UNITS
  DATABASE MICRONS 1000 ;
END UNITS


VERSION 5.7 ;
NAMESCASESENSITIVE ON ;
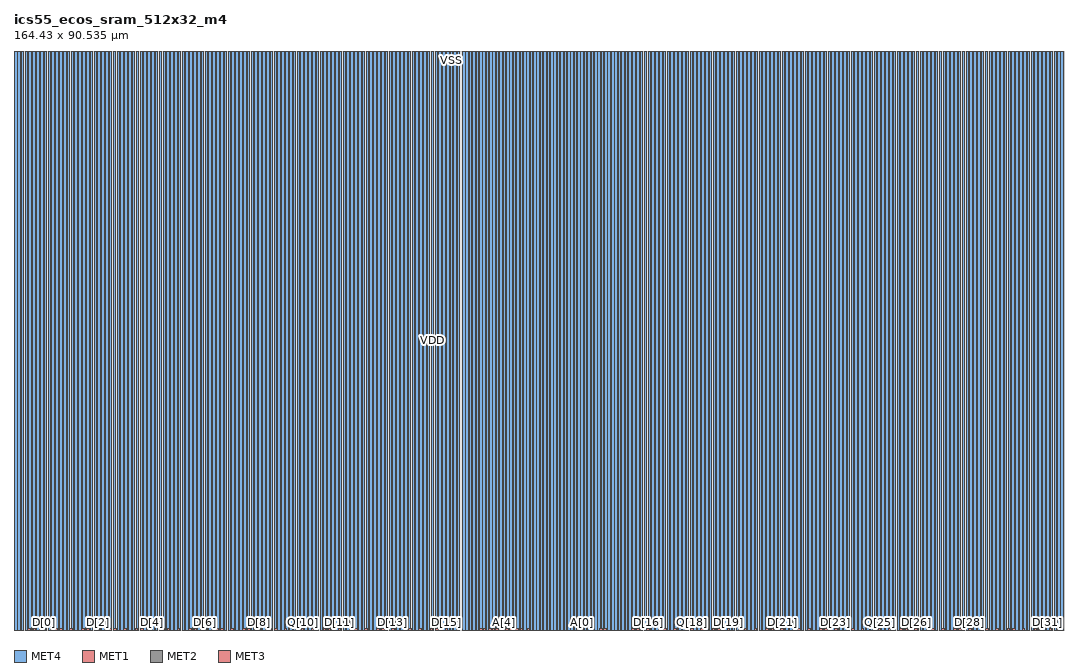
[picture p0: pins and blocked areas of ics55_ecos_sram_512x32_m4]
MACRO ics55_ecos_sram_512x32_m4
CLASS BLOCK ;
FOREIGN ics55_ecos_sram_512x32_m4 0.000 0.000 ;
ORIGIN 0.000 0.000 ;
SIZE 164.430 BY 90.535 ;
SYMMETRY X Y R90 ;

PIN VDD
  DIRECTION INOUT ;
  USE POWER ;
  PORT
    LAYER MET4 ;
    RECT 0.605 0.000 1.015 90.535 ;
    RECT 1.735 0.000 2.145 90.535 ;
    RECT 2.335 0.000 2.745 90.535 ;
    RECT 3.535 0.000 3.945 90.535 ;
    RECT 4.135 0.000 4.545 90.535 ;
    RECT 4.735 0.000 5.145 90.535 ;
    RECT 5.935 0.000 6.345 90.535 ;
    RECT 6.535 0.000 6.945 90.535 ;
    RECT 7.735 0.000 8.145 90.535 ;
    RECT 8.335 0.000 8.745 90.535 ;
    RECT 8.935 0.000 9.345 90.535 ;
    RECT 10.135 0.000 10.545 90.535 ;
    RECT 10.735 0.000 11.145 90.535 ;
    RECT 11.935 0.000 12.345 90.535 ;
    RECT 12.535 0.000 12.945 90.535 ;
    RECT 13.135 0.000 13.545 90.535 ;
    RECT 14.335 0.000 14.745 90.535 ;
    RECT 14.935 0.000 15.345 90.535 ;
    RECT 16.135 0.000 16.545 90.535 ;
    RECT 16.735 0.000 17.145 90.535 ;
    RECT 17.335 0.000 17.745 90.535 ;
    RECT 18.535 0.000 18.945 90.535 ;
    RECT 19.135 0.000 19.545 90.535 ;
    RECT 20.335 0.000 20.745 90.535 ;
    RECT 20.935 0.000 21.345 90.535 ;
    RECT 21.535 0.000 21.945 90.535 ;
    RECT 22.735 0.000 23.145 90.535 ;
    RECT 23.335 0.000 23.745 90.535 ;
    RECT 24.535 0.000 24.945 90.535 ;
    RECT 25.135 0.000 25.545 90.535 ;
    RECT 25.735 0.000 26.145 90.535 ;
    RECT 26.935 0.000 27.345 90.535 ;
    RECT 27.535 0.000 27.945 90.535 ;
    RECT 28.735 0.000 29.145 90.535 ;
    RECT 29.335 0.000 29.745 90.535 ;
    RECT 29.935 0.000 30.345 90.535 ;
    RECT 31.135 0.000 31.545 90.535 ;
    RECT 31.735 0.000 32.145 90.535 ;
    RECT 32.935 0.000 33.345 90.535 ;
    RECT 33.535 0.000 33.945 90.535 ;
    RECT 34.135 0.000 34.545 90.535 ;
    RECT 35.335 0.000 35.745 90.535 ;
    RECT 35.935 0.000 36.345 90.535 ;
    RECT 37.135 0.000 37.545 90.535 ;
    RECT 37.735 0.000 38.145 90.535 ;
    RECT 38.335 0.000 38.745 90.535 ;
    RECT 39.535 0.000 39.945 90.535 ;
    RECT 40.135 0.000 40.545 90.535 ;
    RECT 41.335 0.000 41.745 90.535 ;
    RECT 41.935 0.000 42.345 90.535 ;
    RECT 42.535 0.000 42.945 90.535 ;
    RECT 43.735 0.000 44.145 90.535 ;
    RECT 44.335 0.000 44.745 90.535 ;
    RECT 45.535 0.000 45.945 90.535 ;
    RECT 46.135 0.000 46.545 90.535 ;
    RECT 46.735 0.000 47.145 90.535 ;
    RECT 47.935 0.000 48.345 90.535 ;
    RECT 48.535 0.000 48.945 90.535 ;
    RECT 49.735 0.000 50.145 90.535 ;
    RECT 50.335 0.000 50.745 90.535 ;
    RECT 50.935 0.000 51.345 90.535 ;
    RECT 52.135 0.000 52.545 90.535 ;
    RECT 52.735 0.000 53.145 90.535 ;
    RECT 53.935 0.000 54.345 90.535 ;
    RECT 54.535 0.000 54.945 90.535 ;
    RECT 55.135 0.000 55.545 90.535 ;
    RECT 56.335 0.000 56.745 90.535 ;
    RECT 56.935 0.000 57.345 90.535 ;
    RECT 58.135 0.000 58.545 90.535 ;
    RECT 58.735 0.000 59.145 90.535 ;
    RECT 59.335 0.000 59.745 90.535 ;
    RECT 60.535 0.000 60.945 90.535 ;
    RECT 61.135 0.000 61.545 90.535 ;
    RECT 62.335 0.000 62.745 90.535 ;
    RECT 62.935 0.000 63.345 90.535 ;
    RECT 63.535 0.000 63.945 90.535 ;
    RECT 64.735 0.000 65.145 90.535 ;
    RECT 65.335 0.000 65.745 90.535 ;
    RECT 66.535 0.000 66.945 90.535 ;
    RECT 67.135 0.000 67.545 90.535 ;
    RECT 67.735 0.000 68.145 90.535 ;
    RECT 68.865 0.000 69.275 90.535 ;
    RECT 70.760 0.000 71.170 90.535 ;
    RECT 71.290 0.000 71.700 90.535 ;
    RECT 72.350 0.000 72.760 90.535 ;
    RECT 72.880 0.000 73.290 90.535 ;
    RECT 73.940 0.000 74.350 90.535 ;
    RECT 74.470 0.000 74.880 90.535 ;
    RECT 75.530 0.000 75.940 90.535 ;
    RECT 76.060 0.000 76.470 90.535 ;
    RECT 77.120 0.000 77.530 90.535 ;
    RECT 77.650 0.000 78.060 90.535 ;
    RECT 78.710 0.000 79.120 90.535 ;
    RECT 79.240 0.000 79.650 90.535 ;
    RECT 80.300 0.000 80.710 90.535 ;
    RECT 80.830 0.000 81.240 90.535 ;
    RECT 81.890 0.000 82.300 90.535 ;
    RECT 82.420 0.000 82.830 90.535 ;
    RECT 83.480 0.000 83.890 90.535 ;
    RECT 84.010 0.000 84.420 90.535 ;
    RECT 85.070 0.000 85.480 90.535 ;
    RECT 85.600 0.000 86.010 90.535 ;
    RECT 86.660 0.000 87.070 90.535 ;
    RECT 87.190 0.000 87.600 90.535 ;
    RECT 88.250 0.000 88.660 90.535 ;
    RECT 88.780 0.000 89.190 90.535 ;
    RECT 89.840 0.000 90.250 90.535 ;
    RECT 90.370 0.000 90.780 90.535 ;
    RECT 91.430 0.000 91.840 90.535 ;
    RECT 91.960 0.000 92.370 90.535 ;
    RECT 93.020 0.000 93.430 90.535 ;
    RECT 93.550 0.000 93.960 90.535 ;
    RECT 95.155 0.000 95.565 90.535 ;
    RECT 96.285 0.000 96.695 90.535 ;
    RECT 96.885 0.000 97.295 90.535 ;
    RECT 98.085 0.000 98.495 90.535 ;
    RECT 98.685 0.000 99.095 90.535 ;
    RECT 99.285 0.000 99.695 90.535 ;
    RECT 100.485 0.000 100.895 90.535 ;
    RECT 101.085 0.000 101.495 90.535 ;
    RECT 102.285 0.000 102.695 90.535 ;
    RECT 102.885 0.000 103.295 90.535 ;
    RECT 103.485 0.000 103.895 90.535 ;
    RECT 104.685 0.000 105.095 90.535 ;
    RECT 105.285 0.000 105.695 90.535 ;
    RECT 106.485 0.000 106.895 90.535 ;
    RECT 107.085 0.000 107.495 90.535 ;
    RECT 107.685 0.000 108.095 90.535 ;
    RECT 108.885 0.000 109.295 90.535 ;
    RECT 109.485 0.000 109.895 90.535 ;
    RECT 110.685 0.000 111.095 90.535 ;
    RECT 111.285 0.000 111.695 90.535 ;
    RECT 111.885 0.000 112.295 90.535 ;
    RECT 113.085 0.000 113.495 90.535 ;
    RECT 113.685 0.000 114.095 90.535 ;
    RECT 114.885 0.000 115.295 90.535 ;
    RECT 115.485 0.000 115.895 90.535 ;
    RECT 116.085 0.000 116.495 90.535 ;
    RECT 117.285 0.000 117.695 90.535 ;
    RECT 117.885 0.000 118.295 90.535 ;
    RECT 119.085 0.000 119.495 90.535 ;
    RECT 119.685 0.000 120.095 90.535 ;
    RECT 120.285 0.000 120.695 90.535 ;
    RECT 121.485 0.000 121.895 90.535 ;
    RECT 122.085 0.000 122.495 90.535 ;
    RECT 123.285 0.000 123.695 90.535 ;
    RECT 123.885 0.000 124.295 90.535 ;
    RECT 124.485 0.000 124.895 90.535 ;
    RECT 125.685 0.000 126.095 90.535 ;
    RECT 126.285 0.000 126.695 90.535 ;
    RECT 127.485 0.000 127.895 90.535 ;
    RECT 128.085 0.000 128.495 90.535 ;
    RECT 128.685 0.000 129.095 90.535 ;
    RECT 129.885 0.000 130.295 90.535 ;
    RECT 130.485 0.000 130.895 90.535 ;
    RECT 131.685 0.000 132.095 90.535 ;
    RECT 132.285 0.000 132.695 90.535 ;
    RECT 132.885 0.000 133.295 90.535 ;
    RECT 134.085 0.000 134.495 90.535 ;
    RECT 134.685 0.000 135.095 90.535 ;
    RECT 135.885 0.000 136.295 90.535 ;
    RECT 136.485 0.000 136.895 90.535 ;
    RECT 137.085 0.000 137.495 90.535 ;
    RECT 138.285 0.000 138.695 90.535 ;
    RECT 138.885 0.000 139.295 90.535 ;
    RECT 140.085 0.000 140.495 90.535 ;
    RECT 140.685 0.000 141.095 90.535 ;
    RECT 141.285 0.000 141.695 90.535 ;
    RECT 142.485 0.000 142.895 90.535 ;
    RECT 143.085 0.000 143.495 90.535 ;
    RECT 144.285 0.000 144.695 90.535 ;
    RECT 144.885 0.000 145.295 90.535 ;
    RECT 145.485 0.000 145.895 90.535 ;
    RECT 146.685 0.000 147.095 90.535 ;
    RECT 147.285 0.000 147.695 90.535 ;
    RECT 148.485 0.000 148.895 90.535 ;
    RECT 149.085 0.000 149.495 90.535 ;
    RECT 149.685 0.000 150.095 90.535 ;
    RECT 150.885 0.000 151.295 90.535 ;
    RECT 151.485 0.000 151.895 90.535 ;
    RECT 152.685 0.000 153.095 90.535 ;
    RECT 153.285 0.000 153.695 90.535 ;
    RECT 153.885 0.000 154.295 90.535 ;
    RECT 155.085 0.000 155.495 90.535 ;
    RECT 155.685 0.000 156.095 90.535 ;
    RECT 156.885 0.000 157.295 90.535 ;
    RECT 157.485 0.000 157.895 90.535 ;
    RECT 158.085 0.000 158.495 90.535 ;
    RECT 159.285 0.000 159.695 90.535 ;
    RECT 159.885 0.000 160.295 90.535 ;
    RECT 161.085 0.000 161.495 90.535 ;
    RECT 161.685 0.000 162.095 90.535 ;
    RECT 162.285 0.000 162.695 90.535 ;
    RECT 163.415 0.000 163.825 90.535 ;
  END
END VDD

PIN VSS
  DIRECTION INOUT ;
  USE GROUND ;
  PORT
    LAYER MET4 ;
    RECT 0.075 0.000 0.485 90.535 ;
    RECT 1.135 0.000 1.545 90.535 ;
    RECT 2.935 0.000 3.345 90.535 ;
    RECT 5.335 0.000 5.745 90.535 ;
    RECT 7.135 0.000 7.545 90.535 ;
    RECT 9.535 0.000 9.945 90.535 ;
    RECT 11.335 0.000 11.745 90.535 ;
    RECT 13.735 0.000 14.145 90.535 ;
    RECT 15.535 0.000 15.945 90.535 ;
    RECT 17.935 0.000 18.345 90.535 ;
    RECT 19.735 0.000 20.145 90.535 ;
    RECT 22.135 0.000 22.545 90.535 ;
    RECT 23.935 0.000 24.345 90.535 ;
    RECT 26.335 0.000 26.745 90.535 ;
    RECT 28.135 0.000 28.545 90.535 ;
    RECT 30.535 0.000 30.945 90.535 ;
    RECT 32.335 0.000 32.745 90.535 ;
    RECT 34.735 0.000 35.145 90.535 ;
    RECT 36.535 0.000 36.945 90.535 ;
    RECT 38.935 0.000 39.345 90.535 ;
    RECT 40.735 0.000 41.145 90.535 ;
    RECT 43.135 0.000 43.545 90.535 ;
    RECT 44.935 0.000 45.345 90.535 ;
    RECT 47.335 0.000 47.745 90.535 ;
    RECT 49.135 0.000 49.545 90.535 ;
    RECT 51.535 0.000 51.945 90.535 ;
    RECT 53.335 0.000 53.745 90.535 ;
    RECT 55.735 0.000 56.145 90.535 ;
    RECT 57.535 0.000 57.945 90.535 ;
    RECT 59.935 0.000 60.345 90.535 ;
    RECT 61.735 0.000 62.145 90.535 ;
    RECT 64.135 0.000 64.545 90.535 ;
    RECT 65.935 0.000 66.345 90.535 ;
    RECT 68.335 0.000 68.745 90.535 ;
    RECT 69.395 0.000 69.805 90.535 ;
    RECT 70.230 0.000 70.640 90.535 ;
    RECT 71.820 0.000 72.230 90.535 ;
    RECT 73.410 0.000 73.820 90.535 ;
    RECT 75.000 0.000 75.410 90.535 ;
    RECT 76.590 0.000 77.000 90.535 ;
    RECT 78.180 0.000 78.590 90.535 ;
    RECT 79.770 0.000 80.180 90.535 ;
    RECT 81.360 0.000 81.770 90.535 ;
    RECT 82.950 0.000 83.360 90.535 ;
    RECT 84.540 0.000 84.950 90.535 ;
    RECT 86.130 0.000 86.540 90.535 ;
    RECT 87.720 0.000 88.130 90.535 ;
    RECT 89.310 0.000 89.720 90.535 ;
    RECT 90.900 0.000 91.310 90.535 ;
    RECT 92.490 0.000 92.900 90.535 ;
    RECT 94.080 0.000 94.490 90.535 ;
    RECT 94.625 0.000 95.035 90.535 ;
    RECT 95.685 0.000 96.095 90.535 ;
    RECT 97.485 0.000 97.895 90.535 ;
    RECT 99.885 0.000 100.295 90.535 ;
    RECT 101.685 0.000 102.095 90.535 ;
    RECT 104.085 0.000 104.495 90.535 ;
    RECT 105.885 0.000 106.295 90.535 ;
    RECT 108.285 0.000 108.695 90.535 ;
    RECT 110.085 0.000 110.495 90.535 ;
    RECT 112.485 0.000 112.895 90.535 ;
    RECT 114.285 0.000 114.695 90.535 ;
    RECT 116.685 0.000 117.095 90.535 ;
    RECT 118.485 0.000 118.895 90.535 ;
    RECT 120.885 0.000 121.295 90.535 ;
    RECT 122.685 0.000 123.095 90.535 ;
    RECT 125.085 0.000 125.495 90.535 ;
    RECT 126.885 0.000 127.295 90.535 ;
    RECT 129.285 0.000 129.695 90.535 ;
    RECT 131.085 0.000 131.495 90.535 ;
    RECT 133.485 0.000 133.895 90.535 ;
    RECT 135.285 0.000 135.695 90.535 ;
    RECT 137.685 0.000 138.095 90.535 ;
    RECT 139.485 0.000 139.895 90.535 ;
    RECT 141.885 0.000 142.295 90.535 ;
    RECT 143.685 0.000 144.095 90.535 ;
    RECT 146.085 0.000 146.495 90.535 ;
    RECT 147.885 0.000 148.295 90.535 ;
    RECT 150.285 0.000 150.695 90.535 ;
    RECT 152.085 0.000 152.495 90.535 ;
    RECT 154.485 0.000 154.895 90.535 ;
    RECT 156.285 0.000 156.695 90.535 ;
    RECT 158.685 0.000 159.095 90.535 ;
    RECT 160.485 0.000 160.895 90.535 ;
    RECT 162.885 0.000 163.295 90.535 ;
    RECT 163.945 0.000 164.355 90.535 ;
  END
END VSS

PIN D[0]
  DIRECTION INPUT ;
  PORT
    LAYER MET1 ;
    RECT 4.540 0.000 4.950 0.180 ;
    LAYER MET2 ;
    RECT 4.540 0.000 4.950 0.180 ;
    LAYER MET3 ;
    RECT 4.540 0.000 4.950 0.180 ;
  END
  ANTENNADIFFAREA                0.38930         LAYER MET1 ;
  ANTENNADIFFAREA                0.38930         LAYER MET2 ;
  ANTENNADIFFAREA                0.38930         LAYER MET3 ;
  ANTENNAGATEAREA                0.06300         LAYER MET1 ;
  ANTENNAGATEAREA                0.06300         LAYER MET2 ;
  ANTENNAGATEAREA                0.06300         LAYER MET3 ;
  ANTENNAPARTIALMETALAREA        0.09890         LAYER MET1 ;
  ANTENNAPARTIALMETALAREA        0.10380         LAYER MET2 ;
  ANTENNAMAXAREACAR              0.72381         LAYER MET1 ;
  ANTENNAMAXAREACAR              3.54286         LAYER MET2 ;
  ANTENNAMAXAREACAR              4.71429         LAYER MET3 ;
END D[0]
PIN WEB[0]
  DIRECTION INPUT ;
  PORT
    LAYER MET1 ;
    RECT 2.190 0.000 2.600 0.180 ;
    LAYER MET2 ;
    RECT 2.190 0.000 2.600 0.180 ;
    LAYER MET3 ;
    RECT 2.190 0.000 2.600 0.180 ;
  END
  ANTENNADIFFAREA                0.45930         LAYER MET1 ;
  ANTENNADIFFAREA                0.45930         LAYER MET2 ;
  ANTENNADIFFAREA                0.45930         LAYER MET3 ;
  ANTENNAGATEAREA                0.08100         LAYER MET1 ;
  ANTENNAGATEAREA                0.08100         LAYER MET2 ;
  ANTENNAGATEAREA                0.08100         LAYER MET3 ;
  ANTENNAPARTIALMETALAREA        0.14210         LAYER MET1 ;
  ANTENNAPARTIALMETALAREA        0.09360         LAYER MET2 ;
  ANTENNAMAXAREACAR              1.09630         LAYER MET1 ;
  ANTENNAMAXAREACAR              3.16296         LAYER MET2 ;
  ANTENNAMAXAREACAR              4.07407         LAYER MET3 ;
END WEB[0]
PIN Q[0]
  DIRECTION OUTPUT ;
  PORT
    LAYER MET1 ;
    RECT 3.000 0.000 3.410 0.180 ;
    LAYER MET2 ;
    RECT 3.000 0.000 3.410 0.180 ;
    LAYER MET3 ;
    RECT 3.000 0.000 3.410 0.180 ;
  END
  ANTENNADIFFAREA                0.60000         LAYER MET1 ;
  ANTENNADIFFAREA                0.60000         LAYER MET2 ;
  ANTENNADIFFAREA                0.60000         LAYER MET3 ;
  ANTENNAPARTIALMETALAREA        0.94400         LAYER MET1 ;
  ANTENNAPARTIALMETALAREA        1.33320         LAYER MET2 ;
END Q[0]
PIN D[1]
  DIRECTION INPUT ;
  PORT
    LAYER MET1 ;
    RECT 8.740 0.000 9.150 0.180 ;
    LAYER MET2 ;
    RECT 8.740 0.000 9.150 0.180 ;
    LAYER MET3 ;
    RECT 8.740 0.000 9.150 0.180 ;
  END
  ANTENNADIFFAREA                0.38930         LAYER MET1 ;
  ANTENNADIFFAREA                0.38930         LAYER MET2 ;
  ANTENNADIFFAREA                0.38930         LAYER MET3 ;
  ANTENNAGATEAREA                0.06300         LAYER MET1 ;
  ANTENNAGATEAREA                0.06300         LAYER MET2 ;
  ANTENNAGATEAREA                0.06300         LAYER MET3 ;
  ANTENNAPARTIALMETALAREA        0.09890         LAYER MET1 ;
  ANTENNAPARTIALMETALAREA        0.10380         LAYER MET2 ;
  ANTENNAMAXAREACAR              0.72381         LAYER MET1 ;
  ANTENNAMAXAREACAR              3.54286         LAYER MET2 ;
  ANTENNAMAXAREACAR              4.71429         LAYER MET3 ;
END D[1]
PIN Q[1]
  DIRECTION OUTPUT ;
  PORT
    LAYER MET1 ;
    RECT 7.200 0.000 7.610 0.180 ;
    LAYER MET2 ;
    RECT 7.200 0.000 7.610 0.180 ;
    LAYER MET3 ;
    RECT 7.200 0.000 7.610 0.180 ;
  END
  ANTENNADIFFAREA                0.60000         LAYER MET1 ;
  ANTENNADIFFAREA                0.60000         LAYER MET2 ;
  ANTENNADIFFAREA                0.60000         LAYER MET3 ;
  ANTENNAPARTIALMETALAREA        0.94400         LAYER MET1 ;
  ANTENNAPARTIALMETALAREA        1.33320         LAYER MET2 ;
END Q[1]
PIN WEB[1]
  DIRECTION INPUT ;
  PORT
    LAYER MET1 ;
    RECT 6.390 0.000 6.800 0.180 ;
    LAYER MET2 ;
    RECT 6.390 0.000 6.800 0.180 ;
    LAYER MET3 ;
    RECT 6.390 0.000 6.800 0.180 ;
  END
  ANTENNADIFFAREA                0.45930         LAYER MET1 ;
  ANTENNADIFFAREA                0.45930         LAYER MET2 ;
  ANTENNADIFFAREA                0.45930         LAYER MET3 ;
  ANTENNAGATEAREA                0.08100         LAYER MET1 ;
  ANTENNAGATEAREA                0.08100         LAYER MET2 ;
  ANTENNAGATEAREA                0.08100         LAYER MET3 ;
  ANTENNAPARTIALMETALAREA        0.14210         LAYER MET1 ;
  ANTENNAPARTIALMETALAREA        0.09360         LAYER MET2 ;
  ANTENNAMAXAREACAR              1.09630         LAYER MET1 ;
  ANTENNAMAXAREACAR              3.16296         LAYER MET2 ;
  ANTENNAMAXAREACAR              4.07407         LAYER MET3 ;
END WEB[1]
PIN D[2]
  DIRECTION INPUT ;
  PORT
    LAYER MET1 ;
    RECT 12.940 0.000 13.350 0.180 ;
    LAYER MET2 ;
    RECT 12.940 0.000 13.350 0.180 ;
    LAYER MET3 ;
    RECT 12.940 0.000 13.350 0.180 ;
  END
  ANTENNADIFFAREA                0.38930         LAYER MET1 ;
  ANTENNADIFFAREA                0.38930         LAYER MET2 ;
  ANTENNADIFFAREA                0.38930         LAYER MET3 ;
  ANTENNAGATEAREA                0.06300         LAYER MET1 ;
  ANTENNAGATEAREA                0.06300         LAYER MET2 ;
  ANTENNAGATEAREA                0.06300         LAYER MET3 ;
  ANTENNAPARTIALMETALAREA        0.09890         LAYER MET1 ;
  ANTENNAPARTIALMETALAREA        0.10380         LAYER MET2 ;
  ANTENNAMAXAREACAR              0.72381         LAYER MET1 ;
  ANTENNAMAXAREACAR              3.54286         LAYER MET2 ;
  ANTENNAMAXAREACAR              4.71429         LAYER MET3 ;
END D[2]
PIN Q[2]
  DIRECTION OUTPUT ;
  PORT
    LAYER MET1 ;
    RECT 11.400 0.000 11.810 0.180 ;
    LAYER MET2 ;
    RECT 11.400 0.000 11.810 0.180 ;
    LAYER MET3 ;
    RECT 11.400 0.000 11.810 0.180 ;
  END
  ANTENNADIFFAREA                0.60000         LAYER MET1 ;
  ANTENNADIFFAREA                0.60000         LAYER MET2 ;
  ANTENNADIFFAREA                0.60000         LAYER MET3 ;
  ANTENNAPARTIALMETALAREA        0.94400         LAYER MET1 ;
  ANTENNAPARTIALMETALAREA        1.33320         LAYER MET2 ;
END Q[2]
PIN WEB[2]
  DIRECTION INPUT ;
  PORT
    LAYER MET1 ;
    RECT 10.590 0.000 11.000 0.180 ;
    LAYER MET2 ;
    RECT 10.590 0.000 11.000 0.180 ;
    LAYER MET3 ;
    RECT 10.590 0.000 11.000 0.180 ;
  END
  ANTENNADIFFAREA                0.45930         LAYER MET1 ;
  ANTENNADIFFAREA                0.45930         LAYER MET2 ;
  ANTENNADIFFAREA                0.45930         LAYER MET3 ;
  ANTENNAGATEAREA                0.08100         LAYER MET1 ;
  ANTENNAGATEAREA                0.08100         LAYER MET2 ;
  ANTENNAGATEAREA                0.08100         LAYER MET3 ;
  ANTENNAPARTIALMETALAREA        0.14210         LAYER MET1 ;
  ANTENNAPARTIALMETALAREA        0.09360         LAYER MET2 ;
  ANTENNAMAXAREACAR              1.09630         LAYER MET1 ;
  ANTENNAMAXAREACAR              3.16296         LAYER MET2 ;
  ANTENNAMAXAREACAR              4.07407         LAYER MET3 ;
END WEB[2]
PIN WEB[5]
  DIRECTION INPUT ;
  PORT
    LAYER MET1 ;
    RECT 23.190 0.000 23.600 0.180 ;
    LAYER MET2 ;
    RECT 23.190 0.000 23.600 0.180 ;
    LAYER MET3 ;
    RECT 23.190 0.000 23.600 0.180 ;
  END
  ANTENNADIFFAREA                0.45930         LAYER MET1 ;
  ANTENNADIFFAREA                0.45930         LAYER MET2 ;
  ANTENNADIFFAREA                0.45930         LAYER MET3 ;
  ANTENNAGATEAREA                0.08100         LAYER MET1 ;
  ANTENNAGATEAREA                0.08100         LAYER MET2 ;
  ANTENNAGATEAREA                0.08100         LAYER MET3 ;
  ANTENNAPARTIALMETALAREA        0.14210         LAYER MET1 ;
  ANTENNAPARTIALMETALAREA        0.09360         LAYER MET2 ;
  ANTENNAMAXAREACAR              1.09630         LAYER MET1 ;
  ANTENNAMAXAREACAR              3.16296         LAYER MET2 ;
  ANTENNAMAXAREACAR              4.07407         LAYER MET3 ;
END WEB[5]
PIN D[6]
  DIRECTION INPUT ;
  PORT
    LAYER MET1 ;
    RECT 29.740 0.000 30.150 0.180 ;
    LAYER MET2 ;
    RECT 29.740 0.000 30.150 0.180 ;
    LAYER MET3 ;
    RECT 29.740 0.000 30.150 0.180 ;
  END
  ANTENNADIFFAREA                0.38930         LAYER MET1 ;
  ANTENNADIFFAREA                0.38930         LAYER MET2 ;
  ANTENNADIFFAREA                0.38930         LAYER MET3 ;
  ANTENNAGATEAREA                0.06300         LAYER MET1 ;
  ANTENNAGATEAREA                0.06300         LAYER MET2 ;
  ANTENNAGATEAREA                0.06300         LAYER MET3 ;
  ANTENNAPARTIALMETALAREA        0.09890         LAYER MET1 ;
  ANTENNAPARTIALMETALAREA        0.10380         LAYER MET2 ;
  ANTENNAMAXAREACAR              0.72381         LAYER MET1 ;
  ANTENNAMAXAREACAR              3.54286         LAYER MET2 ;
  ANTENNAMAXAREACAR              4.71429         LAYER MET3 ;
END D[6]
PIN D[3]
  DIRECTION INPUT ;
  PORT
    LAYER MET1 ;
    RECT 17.140 0.000 17.550 0.180 ;
    LAYER MET2 ;
    RECT 17.140 0.000 17.550 0.180 ;
    LAYER MET3 ;
    RECT 17.140 0.000 17.550 0.180 ;
  END
  ANTENNADIFFAREA                0.38930         LAYER MET1 ;
  ANTENNADIFFAREA                0.38930         LAYER MET2 ;
  ANTENNADIFFAREA                0.38930         LAYER MET3 ;
  ANTENNAGATEAREA                0.06300         LAYER MET1 ;
  ANTENNAGATEAREA                0.06300         LAYER MET2 ;
  ANTENNAGATEAREA                0.06300         LAYER MET3 ;
  ANTENNAPARTIALMETALAREA        0.09890         LAYER MET1 ;
  ANTENNAPARTIALMETALAREA        0.10380         LAYER MET2 ;
  ANTENNAMAXAREACAR              0.72381         LAYER MET1 ;
  ANTENNAMAXAREACAR              3.54286         LAYER MET2 ;
  ANTENNAMAXAREACAR              4.71429         LAYER MET3 ;
END D[3]
PIN Q[3]
  DIRECTION OUTPUT ;
  PORT
    LAYER MET1 ;
    RECT 15.600 0.000 16.010 0.180 ;
    LAYER MET2 ;
    RECT 15.600 0.000 16.010 0.180 ;
    LAYER MET3 ;
    RECT 15.600 0.000 16.010 0.180 ;
  END
  ANTENNADIFFAREA                0.60000         LAYER MET1 ;
  ANTENNADIFFAREA                0.60000         LAYER MET2 ;
  ANTENNADIFFAREA                0.60000         LAYER MET3 ;
  ANTENNAPARTIALMETALAREA        0.94400         LAYER MET1 ;
  ANTENNAPARTIALMETALAREA        1.33320         LAYER MET2 ;
END Q[3]
PIN WEB[3]
  DIRECTION INPUT ;
  PORT
    LAYER MET1 ;
    RECT 14.790 0.000 15.200 0.180 ;
    LAYER MET2 ;
    RECT 14.790 0.000 15.200 0.180 ;
    LAYER MET3 ;
    RECT 14.790 0.000 15.200 0.180 ;
  END
  ANTENNADIFFAREA                0.45930         LAYER MET1 ;
  ANTENNADIFFAREA                0.45930         LAYER MET2 ;
  ANTENNADIFFAREA                0.45930         LAYER MET3 ;
  ANTENNAGATEAREA                0.08100         LAYER MET1 ;
  ANTENNAGATEAREA                0.08100         LAYER MET2 ;
  ANTENNAGATEAREA                0.08100         LAYER MET3 ;
  ANTENNAPARTIALMETALAREA        0.14210         LAYER MET1 ;
  ANTENNAPARTIALMETALAREA        0.09360         LAYER MET2 ;
  ANTENNAMAXAREACAR              1.09630         LAYER MET1 ;
  ANTENNAMAXAREACAR              3.16296         LAYER MET2 ;
  ANTENNAMAXAREACAR              4.07407         LAYER MET3 ;
END WEB[3]
PIN D[4]
  DIRECTION INPUT ;
  PORT
    LAYER MET1 ;
    RECT 21.340 0.000 21.750 0.180 ;
    LAYER MET2 ;
    RECT 21.340 0.000 21.750 0.180 ;
    LAYER MET3 ;
    RECT 21.340 0.000 21.750 0.180 ;
  END
  ANTENNADIFFAREA                0.38930         LAYER MET1 ;
  ANTENNADIFFAREA                0.38930         LAYER MET2 ;
  ANTENNADIFFAREA                0.38930         LAYER MET3 ;
  ANTENNAGATEAREA                0.06300         LAYER MET1 ;
  ANTENNAGATEAREA                0.06300         LAYER MET2 ;
  ANTENNAGATEAREA                0.06300         LAYER MET3 ;
  ANTENNAPARTIALMETALAREA        0.09890         LAYER MET1 ;
  ANTENNAPARTIALMETALAREA        0.10380         LAYER MET2 ;
  ANTENNAMAXAREACAR              0.72381         LAYER MET1 ;
  ANTENNAMAXAREACAR              3.54286         LAYER MET2 ;
  ANTENNAMAXAREACAR              4.71429         LAYER MET3 ;
END D[4]
PIN Q[4]
  DIRECTION OUTPUT ;
  PORT
    LAYER MET1 ;
    RECT 19.800 0.000 20.210 0.180 ;
    LAYER MET2 ;
    RECT 19.800 0.000 20.210 0.180 ;
    LAYER MET3 ;
    RECT 19.800 0.000 20.210 0.180 ;
  END
  ANTENNADIFFAREA                0.60000         LAYER MET1 ;
  ANTENNADIFFAREA                0.60000         LAYER MET2 ;
  ANTENNADIFFAREA                0.60000         LAYER MET3 ;
  ANTENNAPARTIALMETALAREA        0.94400         LAYER MET1 ;
  ANTENNAPARTIALMETALAREA        1.33320         LAYER MET2 ;
END Q[4]
PIN WEB[4]
  DIRECTION INPUT ;
  PORT
    LAYER MET1 ;
    RECT 18.990 0.000 19.400 0.180 ;
    LAYER MET2 ;
    RECT 18.990 0.000 19.400 0.180 ;
    LAYER MET3 ;
    RECT 18.990 0.000 19.400 0.180 ;
  END
  ANTENNADIFFAREA                0.45930         LAYER MET1 ;
  ANTENNADIFFAREA                0.45930         LAYER MET2 ;
  ANTENNADIFFAREA                0.45930         LAYER MET3 ;
  ANTENNAGATEAREA                0.08100         LAYER MET1 ;
  ANTENNAGATEAREA                0.08100         LAYER MET2 ;
  ANTENNAGATEAREA                0.08100         LAYER MET3 ;
  ANTENNAPARTIALMETALAREA        0.14210         LAYER MET1 ;
  ANTENNAPARTIALMETALAREA        0.09360         LAYER MET2 ;
  ANTENNAMAXAREACAR              1.09630         LAYER MET1 ;
  ANTENNAMAXAREACAR              3.16296         LAYER MET2 ;
  ANTENNAMAXAREACAR              4.07407         LAYER MET3 ;
END WEB[4]
PIN D[5]
  DIRECTION INPUT ;
  PORT
    LAYER MET1 ;
    RECT 25.540 0.000 25.950 0.180 ;
    LAYER MET2 ;
    RECT 25.540 0.000 25.950 0.180 ;
    LAYER MET3 ;
    RECT 25.540 0.000 25.950 0.180 ;
  END
  ANTENNADIFFAREA                0.38930         LAYER MET1 ;
  ANTENNADIFFAREA                0.38930         LAYER MET2 ;
  ANTENNADIFFAREA                0.38930         LAYER MET3 ;
  ANTENNAGATEAREA                0.06300         LAYER MET1 ;
  ANTENNAGATEAREA                0.06300         LAYER MET2 ;
  ANTENNAGATEAREA                0.06300         LAYER MET3 ;
  ANTENNAPARTIALMETALAREA        0.09890         LAYER MET1 ;
  ANTENNAPARTIALMETALAREA        0.10380         LAYER MET2 ;
  ANTENNAMAXAREACAR              0.72381         LAYER MET1 ;
  ANTENNAMAXAREACAR              3.54286         LAYER MET2 ;
  ANTENNAMAXAREACAR              4.71429         LAYER MET3 ;
END D[5]
PIN Q[5]
  DIRECTION OUTPUT ;
  PORT
    LAYER MET1 ;
    RECT 24.000 0.000 24.410 0.180 ;
    LAYER MET2 ;
    RECT 24.000 0.000 24.410 0.180 ;
    LAYER MET3 ;
    RECT 24.000 0.000 24.410 0.180 ;
  END
  ANTENNADIFFAREA                0.60000         LAYER MET1 ;
  ANTENNADIFFAREA                0.60000         LAYER MET2 ;
  ANTENNADIFFAREA                0.60000         LAYER MET3 ;
  ANTENNAPARTIALMETALAREA        0.94400         LAYER MET1 ;
  ANTENNAPARTIALMETALAREA        1.33320         LAYER MET2 ;
END Q[5]
PIN D[11]
  DIRECTION INPUT ;
  PORT
    LAYER MET1 ;
    RECT 50.740 0.000 51.150 0.180 ;
    LAYER MET2 ;
    RECT 50.740 0.000 51.150 0.180 ;
    LAYER MET3 ;
    RECT 50.740 0.000 51.150 0.180 ;
  END
  ANTENNADIFFAREA                0.38930         LAYER MET1 ;
  ANTENNADIFFAREA                0.38930         LAYER MET2 ;
  ANTENNADIFFAREA                0.38930         LAYER MET3 ;
  ANTENNAGATEAREA                0.06300         LAYER MET1 ;
  ANTENNAGATEAREA                0.06300         LAYER MET2 ;
  ANTENNAGATEAREA                0.06300         LAYER MET3 ;
  ANTENNAPARTIALMETALAREA        0.09890         LAYER MET1 ;
  ANTENNAPARTIALMETALAREA        0.10380         LAYER MET2 ;
  ANTENNAMAXAREACAR              0.72381         LAYER MET1 ;
  ANTENNAMAXAREACAR              3.54286         LAYER MET2 ;
  ANTENNAMAXAREACAR              4.71429         LAYER MET3 ;
END D[11]
PIN Q[6]
  DIRECTION OUTPUT ;
  PORT
    LAYER MET1 ;
    RECT 28.200 0.000 28.610 0.180 ;
    LAYER MET2 ;
    RECT 28.200 0.000 28.610 0.180 ;
    LAYER MET3 ;
    RECT 28.200 0.000 28.610 0.180 ;
  END
  ANTENNADIFFAREA                0.60000         LAYER MET1 ;
  ANTENNADIFFAREA                0.60000         LAYER MET2 ;
  ANTENNADIFFAREA                0.60000         LAYER MET3 ;
  ANTENNAPARTIALMETALAREA        0.94400         LAYER MET1 ;
  ANTENNAPARTIALMETALAREA        1.33320         LAYER MET2 ;
END Q[6]
PIN WEB[6]
  DIRECTION INPUT ;
  PORT
    LAYER MET1 ;
    RECT 27.390 0.000 27.800 0.180 ;
    LAYER MET2 ;
    RECT 27.390 0.000 27.800 0.180 ;
    LAYER MET3 ;
    RECT 27.390 0.000 27.800 0.180 ;
  END
  ANTENNADIFFAREA                0.45930         LAYER MET1 ;
  ANTENNADIFFAREA                0.45930         LAYER MET2 ;
  ANTENNADIFFAREA                0.45930         LAYER MET3 ;
  ANTENNAGATEAREA                0.08100         LAYER MET1 ;
  ANTENNAGATEAREA                0.08100         LAYER MET2 ;
  ANTENNAGATEAREA                0.08100         LAYER MET3 ;
  ANTENNAPARTIALMETALAREA        0.14210         LAYER MET1 ;
  ANTENNAPARTIALMETALAREA        0.09360         LAYER MET2 ;
  ANTENNAMAXAREACAR              1.09630         LAYER MET1 ;
  ANTENNAMAXAREACAR              3.16296         LAYER MET2 ;
  ANTENNAMAXAREACAR              4.07407         LAYER MET3 ;
END WEB[6]
PIN D[7]
  DIRECTION INPUT ;
  PORT
    LAYER MET1 ;
    RECT 33.940 0.000 34.350 0.180 ;
    LAYER MET2 ;
    RECT 33.940 0.000 34.350 0.180 ;
    LAYER MET3 ;
    RECT 33.940 0.000 34.350 0.180 ;
  END
  ANTENNADIFFAREA                0.38930         LAYER MET1 ;
  ANTENNADIFFAREA                0.38930         LAYER MET2 ;
  ANTENNADIFFAREA                0.38930         LAYER MET3 ;
  ANTENNAGATEAREA                0.06300         LAYER MET1 ;
  ANTENNAGATEAREA                0.06300         LAYER MET2 ;
  ANTENNAGATEAREA                0.06300         LAYER MET3 ;
  ANTENNAPARTIALMETALAREA        0.09890         LAYER MET1 ;
  ANTENNAPARTIALMETALAREA        0.10380         LAYER MET2 ;
  ANTENNAMAXAREACAR              0.72381         LAYER MET1 ;
  ANTENNAMAXAREACAR              3.54286         LAYER MET2 ;
  ANTENNAMAXAREACAR              4.71429         LAYER MET3 ;
END D[7]
PIN Q[7]
  DIRECTION OUTPUT ;
  PORT
    LAYER MET1 ;
    RECT 32.400 0.000 32.810 0.180 ;
    LAYER MET2 ;
    RECT 32.400 0.000 32.810 0.180 ;
    LAYER MET3 ;
    RECT 32.400 0.000 32.810 0.180 ;
  END
  ANTENNADIFFAREA                0.60000         LAYER MET1 ;
  ANTENNADIFFAREA                0.60000         LAYER MET2 ;
  ANTENNADIFFAREA                0.60000         LAYER MET3 ;
  ANTENNAPARTIALMETALAREA        0.94400         LAYER MET1 ;
  ANTENNAPARTIALMETALAREA        1.33320         LAYER MET2 ;
END Q[7]
PIN WEB[7]
  DIRECTION INPUT ;
  PORT
    LAYER MET1 ;
    RECT 31.590 0.000 32.000 0.180 ;
    LAYER MET2 ;
    RECT 31.590 0.000 32.000 0.180 ;
    LAYER MET3 ;
    RECT 31.590 0.000 32.000 0.180 ;
  END
  ANTENNADIFFAREA                0.45930         LAYER MET1 ;
  ANTENNADIFFAREA                0.45930         LAYER MET2 ;
  ANTENNADIFFAREA                0.45930         LAYER MET3 ;
  ANTENNAGATEAREA                0.08100         LAYER MET1 ;
  ANTENNAGATEAREA                0.08100         LAYER MET2 ;
  ANTENNAGATEAREA                0.08100         LAYER MET3 ;
  ANTENNAPARTIALMETALAREA        0.14210         LAYER MET1 ;
  ANTENNAPARTIALMETALAREA        0.09360         LAYER MET2 ;
  ANTENNAMAXAREACAR              1.09630         LAYER MET1 ;
  ANTENNAMAXAREACAR              3.16296         LAYER MET2 ;
  ANTENNAMAXAREACAR              4.07407         LAYER MET3 ;
END WEB[7]
PIN D[8]
  DIRECTION INPUT ;
  PORT
    LAYER MET1 ;
    RECT 38.140 0.000 38.550 0.180 ;
    LAYER MET2 ;
    RECT 38.140 0.000 38.550 0.180 ;
    LAYER MET3 ;
    RECT 38.140 0.000 38.550 0.180 ;
  END
  ANTENNADIFFAREA                0.38930         LAYER MET1 ;
  ANTENNADIFFAREA                0.38930         LAYER MET2 ;
  ANTENNADIFFAREA                0.38930         LAYER MET3 ;
  ANTENNAGATEAREA                0.06300         LAYER MET1 ;
  ANTENNAGATEAREA                0.06300         LAYER MET2 ;
  ANTENNAGATEAREA                0.06300         LAYER MET3 ;
  ANTENNAPARTIALMETALAREA        0.09890         LAYER MET1 ;
  ANTENNAPARTIALMETALAREA        0.10380         LAYER MET2 ;
  ANTENNAMAXAREACAR              0.72381         LAYER MET1 ;
  ANTENNAMAXAREACAR              3.54286         LAYER MET2 ;
  ANTENNAMAXAREACAR              4.71429         LAYER MET3 ;
END D[8]
PIN Q[8]
  DIRECTION OUTPUT ;
  PORT
    LAYER MET1 ;
    RECT 36.600 0.000 37.010 0.180 ;
    LAYER MET2 ;
    RECT 36.600 0.000 37.010 0.180 ;
    LAYER MET3 ;
    RECT 36.600 0.000 37.010 0.180 ;
  END
  ANTENNADIFFAREA                0.60000         LAYER MET1 ;
  ANTENNADIFFAREA                0.60000         LAYER MET2 ;
  ANTENNADIFFAREA                0.60000         LAYER MET3 ;
  ANTENNAPARTIALMETALAREA        0.94400         LAYER MET1 ;
  ANTENNAPARTIALMETALAREA        1.33320         LAYER MET2 ;
END Q[8]
PIN WEB[8]
  DIRECTION INPUT ;
  PORT
    LAYER MET1 ;
    RECT 35.790 0.000 36.200 0.180 ;
    LAYER MET2 ;
    RECT 35.790 0.000 36.200 0.180 ;
    LAYER MET3 ;
    RECT 35.790 0.000 36.200 0.180 ;
  END
  ANTENNADIFFAREA                0.45930         LAYER MET1 ;
  ANTENNADIFFAREA                0.45930         LAYER MET2 ;
  ANTENNADIFFAREA                0.45930         LAYER MET3 ;
  ANTENNAGATEAREA                0.08100         LAYER MET1 ;
  ANTENNAGATEAREA                0.08100         LAYER MET2 ;
  ANTENNAGATEAREA                0.08100         LAYER MET3 ;
  ANTENNAPARTIALMETALAREA        0.14210         LAYER MET1 ;
  ANTENNAPARTIALMETALAREA        0.09360         LAYER MET2 ;
  ANTENNAMAXAREACAR              1.09630         LAYER MET1 ;
  ANTENNAMAXAREACAR              3.16296         LAYER MET2 ;
  ANTENNAMAXAREACAR              4.07407         LAYER MET3 ;
END WEB[8]
PIN D[9]
  DIRECTION INPUT ;
  PORT
    LAYER MET1 ;
    RECT 42.340 0.000 42.750 0.180 ;
    LAYER MET2 ;
    RECT 42.340 0.000 42.750 0.180 ;
    LAYER MET3 ;
    RECT 42.340 0.000 42.750 0.180 ;
  END
  ANTENNADIFFAREA                0.38930         LAYER MET1 ;
  ANTENNADIFFAREA                0.38930         LAYER MET2 ;
  ANTENNADIFFAREA                0.38930         LAYER MET3 ;
  ANTENNAGATEAREA                0.06300         LAYER MET1 ;
  ANTENNAGATEAREA                0.06300         LAYER MET2 ;
  ANTENNAGATEAREA                0.06300         LAYER MET3 ;
  ANTENNAPARTIALMETALAREA        0.09890         LAYER MET1 ;
  ANTENNAPARTIALMETALAREA        0.10380         LAYER MET2 ;
  ANTENNAMAXAREACAR              0.72381         LAYER MET1 ;
  ANTENNAMAXAREACAR              3.54286         LAYER MET2 ;
  ANTENNAMAXAREACAR              4.71429         LAYER MET3 ;
END D[9]
PIN Q[9]
  DIRECTION OUTPUT ;
  PORT
    LAYER MET1 ;
    RECT 40.800 0.000 41.210 0.180 ;
    LAYER MET2 ;
    RECT 40.800 0.000 41.210 0.180 ;
    LAYER MET3 ;
    RECT 40.800 0.000 41.210 0.180 ;
  END
  ANTENNADIFFAREA                0.60000         LAYER MET1 ;
  ANTENNADIFFAREA                0.60000         LAYER MET2 ;
  ANTENNADIFFAREA                0.60000         LAYER MET3 ;
  ANTENNAPARTIALMETALAREA        0.94400         LAYER MET1 ;
  ANTENNAPARTIALMETALAREA        1.33320         LAYER MET2 ;
END Q[9]
PIN WEB[9]
  DIRECTION INPUT ;
  PORT
    LAYER MET1 ;
    RECT 39.990 0.000 40.400 0.180 ;
    LAYER MET2 ;
    RECT 39.990 0.000 40.400 0.180 ;
    LAYER MET3 ;
    RECT 39.990 0.000 40.400 0.180 ;
  END
  ANTENNADIFFAREA                0.45930         LAYER MET1 ;
  ANTENNADIFFAREA                0.45930         LAYER MET2 ;
  ANTENNADIFFAREA                0.45930         LAYER MET3 ;
  ANTENNAGATEAREA                0.08100         LAYER MET1 ;
  ANTENNAGATEAREA                0.08100         LAYER MET2 ;
  ANTENNAGATEAREA                0.08100         LAYER MET3 ;
  ANTENNAPARTIALMETALAREA        0.14210         LAYER MET1 ;
  ANTENNAPARTIALMETALAREA        0.09360         LAYER MET2 ;
  ANTENNAMAXAREACAR              1.09630         LAYER MET1 ;
  ANTENNAMAXAREACAR              3.16296         LAYER MET2 ;
  ANTENNAMAXAREACAR              4.07407         LAYER MET3 ;
END WEB[9]
PIN D[10]
  DIRECTION INPUT ;
  PORT
    LAYER MET1 ;
    RECT 46.540 0.000 46.950 0.180 ;
    LAYER MET2 ;
    RECT 46.540 0.000 46.950 0.180 ;
    LAYER MET3 ;
    RECT 46.540 0.000 46.950 0.180 ;
  END
  ANTENNADIFFAREA                0.38930         LAYER MET1 ;
  ANTENNADIFFAREA                0.38930         LAYER MET2 ;
  ANTENNADIFFAREA                0.38930         LAYER MET3 ;
  ANTENNAGATEAREA                0.06300         LAYER MET1 ;
  ANTENNAGATEAREA                0.06300         LAYER MET2 ;
  ANTENNAGATEAREA                0.06300         LAYER MET3 ;
  ANTENNAPARTIALMETALAREA        0.09890         LAYER MET1 ;
  ANTENNAPARTIALMETALAREA        0.10380         LAYER MET2 ;
  ANTENNAMAXAREACAR              0.72381         LAYER MET1 ;
  ANTENNAMAXAREACAR              3.54286         LAYER MET2 ;
  ANTENNAMAXAREACAR              4.71429         LAYER MET3 ;
END D[10]
PIN Q[10]
  DIRECTION OUTPUT ;
  PORT
    LAYER MET1 ;
    RECT 45.000 0.000 45.410 0.180 ;
    LAYER MET2 ;
    RECT 45.000 0.000 45.410 0.180 ;
    LAYER MET3 ;
    RECT 45.000 0.000 45.410 0.180 ;
  END
  ANTENNADIFFAREA                0.60000         LAYER MET1 ;
  ANTENNADIFFAREA                0.60000         LAYER MET2 ;
  ANTENNADIFFAREA                0.60000         LAYER MET3 ;
  ANTENNAPARTIALMETALAREA        0.94400         LAYER MET1 ;
  ANTENNAPARTIALMETALAREA        1.33320         LAYER MET2 ;
END Q[10]
PIN WEB[10]
  DIRECTION INPUT ;
  PORT
    LAYER MET1 ;
    RECT 44.190 0.000 44.600 0.180 ;
    LAYER MET2 ;
    RECT 44.190 0.000 44.600 0.180 ;
    LAYER MET3 ;
    RECT 44.190 0.000 44.600 0.180 ;
  END
  ANTENNADIFFAREA                0.45930         LAYER MET1 ;
  ANTENNADIFFAREA                0.45930         LAYER MET2 ;
  ANTENNADIFFAREA                0.45930         LAYER MET3 ;
  ANTENNAGATEAREA                0.08100         LAYER MET1 ;
  ANTENNAGATEAREA                0.08100         LAYER MET2 ;
  ANTENNAGATEAREA                0.08100         LAYER MET3 ;
  ANTENNAPARTIALMETALAREA        0.14210         LAYER MET1 ;
  ANTENNAPARTIALMETALAREA        0.09360         LAYER MET2 ;
  ANTENNAMAXAREACAR              1.09630         LAYER MET1 ;
  ANTENNAMAXAREACAR              3.16296         LAYER MET2 ;
  ANTENNAMAXAREACAR              4.07407         LAYER MET3 ;
END WEB[10]
PIN Q[11]
  DIRECTION OUTPUT ;
  PORT
    LAYER MET1 ;
    RECT 49.200 0.000 49.610 0.180 ;
    LAYER MET2 ;
    RECT 49.200 0.000 49.610 0.180 ;
    LAYER MET3 ;
    RECT 49.200 0.000 49.610 0.180 ;
  END
  ANTENNADIFFAREA                0.60000         LAYER MET1 ;
  ANTENNADIFFAREA                0.60000         LAYER MET2 ;
  ANTENNADIFFAREA                0.60000         LAYER MET3 ;
  ANTENNAPARTIALMETALAREA        0.94400         LAYER MET1 ;
  ANTENNAPARTIALMETALAREA        1.33320         LAYER MET2 ;
END Q[11]
PIN WEB[11]
  DIRECTION INPUT ;
  PORT
    LAYER MET1 ;
    RECT 48.390 0.000 48.800 0.180 ;
    LAYER MET2 ;
    RECT 48.390 0.000 48.800 0.180 ;
    LAYER MET3 ;
    RECT 48.390 0.000 48.800 0.180 ;
  END
  ANTENNADIFFAREA                0.45930         LAYER MET1 ;
  ANTENNADIFFAREA                0.45930         LAYER MET2 ;
  ANTENNADIFFAREA                0.45930         LAYER MET3 ;
  ANTENNAGATEAREA                0.08100         LAYER MET1 ;
  ANTENNAGATEAREA                0.08100         LAYER MET2 ;
  ANTENNAGATEAREA                0.08100         LAYER MET3 ;
  ANTENNAPARTIALMETALAREA        0.14210         LAYER MET1 ;
  ANTENNAPARTIALMETALAREA        0.09360         LAYER MET2 ;
  ANTENNAMAXAREACAR              1.09630         LAYER MET1 ;
  ANTENNAMAXAREACAR              3.16296         LAYER MET2 ;
  ANTENNAMAXAREACAR              4.07407         LAYER MET3 ;
END WEB[11]
PIN D[12]
  DIRECTION INPUT ;
  PORT
    LAYER MET1 ;
    RECT 54.940 0.000 55.350 0.180 ;
    LAYER MET2 ;
    RECT 54.940 0.000 55.350 0.180 ;
    LAYER MET3 ;
    RECT 54.940 0.000 55.350 0.180 ;
  END
  ANTENNADIFFAREA                0.38930         LAYER MET1 ;
  ANTENNADIFFAREA                0.38930         LAYER MET2 ;
  ANTENNADIFFAREA                0.38930         LAYER MET3 ;
  ANTENNAGATEAREA                0.06300         LAYER MET1 ;
  ANTENNAGATEAREA                0.06300         LAYER MET2 ;
  ANTENNAGATEAREA                0.06300         LAYER MET3 ;
  ANTENNAPARTIALMETALAREA        0.09890         LAYER MET1 ;
  ANTENNAPARTIALMETALAREA        0.10380         LAYER MET2 ;
  ANTENNAMAXAREACAR              0.72381         LAYER MET1 ;
  ANTENNAMAXAREACAR              3.54286         LAYER MET2 ;
  ANTENNAMAXAREACAR              4.71429         LAYER MET3 ;
END D[12]
PIN Q[12]
  DIRECTION OUTPUT ;
  PORT
    LAYER MET1 ;
    RECT 53.400 0.000 53.810 0.180 ;
    LAYER MET2 ;
    RECT 53.400 0.000 53.810 0.180 ;
    LAYER MET3 ;
    RECT 53.400 0.000 53.810 0.180 ;
  END
  ANTENNADIFFAREA                0.60000         LAYER MET1 ;
  ANTENNADIFFAREA                0.60000         LAYER MET2 ;
  ANTENNADIFFAREA                0.60000         LAYER MET3 ;
  ANTENNAPARTIALMETALAREA        0.94400         LAYER MET1 ;
  ANTENNAPARTIALMETALAREA        1.33320         LAYER MET2 ;
END Q[12]
PIN WEB[12]
  DIRECTION INPUT ;
  PORT
    LAYER MET1 ;
    RECT 52.590 0.000 53.000 0.180 ;
    LAYER MET2 ;
    RECT 52.590 0.000 53.000 0.180 ;
    LAYER MET3 ;
    RECT 52.590 0.000 53.000 0.180 ;
  END
  ANTENNADIFFAREA                0.45930         LAYER MET1 ;
  ANTENNADIFFAREA                0.45930         LAYER MET2 ;
  ANTENNADIFFAREA                0.45930         LAYER MET3 ;
  ANTENNAGATEAREA                0.08100         LAYER MET1 ;
  ANTENNAGATEAREA                0.08100         LAYER MET2 ;
  ANTENNAGATEAREA                0.08100         LAYER MET3 ;
  ANTENNAPARTIALMETALAREA        0.14210         LAYER MET1 ;
  ANTENNAPARTIALMETALAREA        0.09360         LAYER MET2 ;
  ANTENNAMAXAREACAR              1.09630         LAYER MET1 ;
  ANTENNAMAXAREACAR              3.16296         LAYER MET2 ;
  ANTENNAMAXAREACAR              4.07407         LAYER MET3 ;
END WEB[12]
PIN D[13]
  DIRECTION INPUT ;
  PORT
    LAYER MET1 ;
    RECT 59.140 0.000 59.550 0.180 ;
    LAYER MET2 ;
    RECT 59.140 0.000 59.550 0.180 ;
    LAYER MET3 ;
    RECT 59.140 0.000 59.550 0.180 ;
  END
  ANTENNADIFFAREA                0.38930         LAYER MET1 ;
  ANTENNADIFFAREA                0.38930         LAYER MET2 ;
  ANTENNADIFFAREA                0.38930         LAYER MET3 ;
  ANTENNAGATEAREA                0.06300         LAYER MET1 ;
  ANTENNAGATEAREA                0.06300         LAYER MET2 ;
  ANTENNAGATEAREA                0.06300         LAYER MET3 ;
  ANTENNAPARTIALMETALAREA        0.09890         LAYER MET1 ;
  ANTENNAPARTIALMETALAREA        0.10380         LAYER MET2 ;
  ANTENNAMAXAREACAR              0.72381         LAYER MET1 ;
  ANTENNAMAXAREACAR              3.54286         LAYER MET2 ;
  ANTENNAMAXAREACAR              4.71429         LAYER MET3 ;
END D[13]
PIN Q[13]
  DIRECTION OUTPUT ;
  PORT
    LAYER MET1 ;
    RECT 57.600 0.000 58.010 0.180 ;
    LAYER MET2 ;
    RECT 57.600 0.000 58.010 0.180 ;
    LAYER MET3 ;
    RECT 57.600 0.000 58.010 0.180 ;
  END
  ANTENNADIFFAREA                0.60000         LAYER MET1 ;
  ANTENNADIFFAREA                0.60000         LAYER MET2 ;
  ANTENNADIFFAREA                0.60000         LAYER MET3 ;
  ANTENNAPARTIALMETALAREA        0.94400         LAYER MET1 ;
  ANTENNAPARTIALMETALAREA        1.33320         LAYER MET2 ;
END Q[13]
PIN WEB[13]
  DIRECTION INPUT ;
  PORT
    LAYER MET1 ;
    RECT 56.790 0.000 57.200 0.180 ;
    LAYER MET2 ;
    RECT 56.790 0.000 57.200 0.180 ;
    LAYER MET3 ;
    RECT 56.790 0.000 57.200 0.180 ;
  END
  ANTENNADIFFAREA                0.45930         LAYER MET1 ;
  ANTENNADIFFAREA                0.45930         LAYER MET2 ;
  ANTENNADIFFAREA                0.45930         LAYER MET3 ;
  ANTENNAGATEAREA                0.08100         LAYER MET1 ;
  ANTENNAGATEAREA                0.08100         LAYER MET2 ;
  ANTENNAGATEAREA                0.08100         LAYER MET3 ;
  ANTENNAPARTIALMETALAREA        0.14210         LAYER MET1 ;
  ANTENNAPARTIALMETALAREA        0.09360         LAYER MET2 ;
  ANTENNAMAXAREACAR              1.09630         LAYER MET1 ;
  ANTENNAMAXAREACAR              3.16296         LAYER MET2 ;
  ANTENNAMAXAREACAR              4.07407         LAYER MET3 ;
END WEB[13]
PIN D[14]
  DIRECTION INPUT ;
  PORT
    LAYER MET1 ;
    RECT 63.340 0.000 63.750 0.180 ;
    LAYER MET2 ;
    RECT 63.340 0.000 63.750 0.180 ;
    LAYER MET3 ;
    RECT 63.340 0.000 63.750 0.180 ;
  END
  ANTENNADIFFAREA                0.38930         LAYER MET1 ;
  ANTENNADIFFAREA                0.38930         LAYER MET2 ;
  ANTENNADIFFAREA                0.38930         LAYER MET3 ;
  ANTENNAGATEAREA                0.06300         LAYER MET1 ;
  ANTENNAGATEAREA                0.06300         LAYER MET2 ;
  ANTENNAGATEAREA                0.06300         LAYER MET3 ;
  ANTENNAPARTIALMETALAREA        0.09890         LAYER MET1 ;
  ANTENNAPARTIALMETALAREA        0.10380         LAYER MET2 ;
  ANTENNAMAXAREACAR              0.72381         LAYER MET1 ;
  ANTENNAMAXAREACAR              3.54286         LAYER MET2 ;
  ANTENNAMAXAREACAR              4.71429         LAYER MET3 ;
END D[14]
PIN Q[14]
  DIRECTION OUTPUT ;
  PORT
    LAYER MET1 ;
    RECT 61.800 0.000 62.210 0.180 ;
    LAYER MET2 ;
    RECT 61.800 0.000 62.210 0.180 ;
    LAYER MET3 ;
    RECT 61.800 0.000 62.210 0.180 ;
  END
  ANTENNADIFFAREA                0.60000         LAYER MET1 ;
  ANTENNADIFFAREA                0.60000         LAYER MET2 ;
  ANTENNADIFFAREA                0.60000         LAYER MET3 ;
  ANTENNAPARTIALMETALAREA        0.94400         LAYER MET1 ;
  ANTENNAPARTIALMETALAREA        1.33320         LAYER MET2 ;
END Q[14]
PIN WEB[14]
  DIRECTION INPUT ;
  PORT
    LAYER MET1 ;
    RECT 60.990 0.000 61.400 0.180 ;
    LAYER MET2 ;
    RECT 60.990 0.000 61.400 0.180 ;
    LAYER MET3 ;
    RECT 60.990 0.000 61.400 0.180 ;
  END
  ANTENNADIFFAREA                0.45930         LAYER MET1 ;
  ANTENNADIFFAREA                0.45930         LAYER MET2 ;
  ANTENNADIFFAREA                0.45930         LAYER MET3 ;
  ANTENNAGATEAREA                0.08100         LAYER MET1 ;
  ANTENNAGATEAREA                0.08100         LAYER MET2 ;
  ANTENNAGATEAREA                0.08100         LAYER MET3 ;
  ANTENNAPARTIALMETALAREA        0.14210         LAYER MET1 ;
  ANTENNAPARTIALMETALAREA        0.09360         LAYER MET2 ;
  ANTENNAMAXAREACAR              1.09630         LAYER MET1 ;
  ANTENNAMAXAREACAR              3.16296         LAYER MET2 ;
  ANTENNAMAXAREACAR              4.07407         LAYER MET3 ;
END WEB[14]
PIN D[15]
  DIRECTION INPUT ;
  PORT
    LAYER MET1 ;
    RECT 67.540 0.000 67.950 0.180 ;
    LAYER MET2 ;
    RECT 67.540 0.000 67.950 0.180 ;
    LAYER MET3 ;
    RECT 67.540 0.000 67.950 0.180 ;
  END
  ANTENNADIFFAREA                0.38930         LAYER MET1 ;
  ANTENNADIFFAREA                0.38930         LAYER MET2 ;
  ANTENNADIFFAREA                0.38930         LAYER MET3 ;
  ANTENNAGATEAREA                0.06300         LAYER MET1 ;
  ANTENNAGATEAREA                0.06300         LAYER MET2 ;
  ANTENNAGATEAREA                0.06300         LAYER MET3 ;
  ANTENNAPARTIALMETALAREA        0.09890         LAYER MET1 ;
  ANTENNAPARTIALMETALAREA        0.10380         LAYER MET2 ;
  ANTENNAMAXAREACAR              0.72381         LAYER MET1 ;
  ANTENNAMAXAREACAR              3.54286         LAYER MET2 ;
  ANTENNAMAXAREACAR              4.71429         LAYER MET3 ;
END D[15]
PIN Q[15]
  DIRECTION OUTPUT ;
  PORT
    LAYER MET1 ;
    RECT 66.000 0.000 66.410 0.180 ;
    LAYER MET2 ;
    RECT 66.000 0.000 66.410 0.180 ;
    LAYER MET3 ;
    RECT 66.000 0.000 66.410 0.180 ;
  END
  ANTENNADIFFAREA                0.60000         LAYER MET1 ;
  ANTENNADIFFAREA                0.60000         LAYER MET2 ;
  ANTENNADIFFAREA                0.60000         LAYER MET3 ;
  ANTENNAPARTIALMETALAREA        0.94400         LAYER MET1 ;
  ANTENNAPARTIALMETALAREA        1.33320         LAYER MET2 ;
END Q[15]
PIN WEB[15]
  DIRECTION INPUT ;
  PORT
    LAYER MET1 ;
    RECT 65.190 0.000 65.600 0.180 ;
    LAYER MET2 ;
    RECT 65.190 0.000 65.600 0.180 ;
    LAYER MET3 ;
    RECT 65.190 0.000 65.600 0.180 ;
  END
  ANTENNADIFFAREA                0.45930         LAYER MET1 ;
  ANTENNADIFFAREA                0.45930         LAYER MET2 ;
  ANTENNADIFFAREA                0.45930         LAYER MET3 ;
  ANTENNAGATEAREA                0.08100         LAYER MET1 ;
  ANTENNAGATEAREA                0.08100         LAYER MET2 ;
  ANTENNAGATEAREA                0.08100         LAYER MET3 ;
  ANTENNAPARTIALMETALAREA        0.14210         LAYER MET1 ;
  ANTENNAPARTIALMETALAREA        0.09360         LAYER MET2 ;
  ANTENNAMAXAREACAR              1.09630         LAYER MET1 ;
  ANTENNAMAXAREACAR              3.16296         LAYER MET2 ;
  ANTENNAMAXAREACAR              4.07407         LAYER MET3 ;
END WEB[15]
PIN CLK
  DIRECTION INPUT ;
  PORT
    LAYER MET1 ;
    RECT 80.390 0.000 80.800 0.180 ;
    LAYER MET2 ;
    RECT 80.390 0.000 80.800 0.180 ;
    LAYER MET3 ;
    RECT 80.390 0.000 80.800 0.180 ;
  END
  ANTENNADIFFAREA                0.68830         LAYER MET1 ;
  ANTENNADIFFAREA                0.68830         LAYER MET2 ;
  ANTENNADIFFAREA                0.68830         LAYER MET3 ;
  ANTENNAGATEAREA                0.09000         LAYER MET1 ;
  ANTENNAGATEAREA                0.09000         LAYER MET2 ;
  ANTENNAGATEAREA                0.09000         LAYER MET3 ;
  ANTENNAPARTIALMETALAREA        0.11410         LAYER MET1 ;
  ANTENNAPARTIALMETALAREA        0.92700         LAYER MET2 ;
  ANTENNAMAXAREACAR              0.67556         LAYER MET1 ;
  ANTENNAMAXAREACAR              11.79556        LAYER MET2 ;
  ANTENNAMAXAREACAR              12.61556        LAYER MET3 ;
END CLK
PIN CEB
  DIRECTION INPUT ;
  PORT
    LAYER MET1 ;
    RECT 78.605 0.000 79.015 0.180 ;
    LAYER MET2 ;
    RECT 78.605 0.000 79.015 0.180 ;
    LAYER MET3 ;
    RECT 78.605 0.000 79.015 0.180 ;
  END
  ANTENNADIFFAREA                2.40880         LAYER MET1 ;
  ANTENNADIFFAREA                2.40880         LAYER MET2 ;
  ANTENNADIFFAREA                2.40880         LAYER MET3 ;
  ANTENNAGATEAREA                0.37800         LAYER MET1 ;
  ANTENNAGATEAREA                0.37800         LAYER MET2 ;
  ANTENNAGATEAREA                0.37800         LAYER MET3 ;
  ANTENNAPARTIALMETALAREA        0.26510         LAYER MET1 ;
  ANTENNAPARTIALMETALAREA        1.07760         LAYER MET2 ;
  ANTENNAMAXAREACAR              3.36190         LAYER MET1 ;
  ANTENNAMAXAREACAR              21.63810        LAYER MET2 ;
  ANTENNAMAXAREACAR              22.80952        LAYER MET3 ;
END CEB
PIN GWEB
  DIRECTION INPUT ;
  PORT
    LAYER MET1 ;
    RECT 78.075 0.000 78.485 0.180 ;
    LAYER MET2 ;
    RECT 78.075 0.000 78.485 0.180 ;
    LAYER MET3 ;
    RECT 78.075 0.000 78.485 0.180 ;
  END
  ANTENNADIFFAREA                0.47330         LAYER MET1 ;
  ANTENNADIFFAREA                0.47330         LAYER MET2 ;
  ANTENNADIFFAREA                0.47330         LAYER MET3 ;
  ANTENNAGATEAREA                0.06300         LAYER MET1 ;
  ANTENNAGATEAREA                0.06300         LAYER MET2 ;
  ANTENNAGATEAREA                0.06300         LAYER MET3 ;
  ANTENNAPARTIALMETALAREA        0.13280         LAYER MET1 ;
  ANTENNAPARTIALMETALAREA        0.98400         LAYER MET2 ;
  ANTENNAMAXAREACAR              1.26190         LAYER MET1 ;
  ANTENNAMAXAREACAR              18.05238        LAYER MET2 ;
  ANTENNAMAXAREACAR              19.22381        LAYER MET3 ;
END GWEB
PIN MARE
  DIRECTION INPUT ;
  PORT
    LAYER MET1 ;
    RECT 73.480 0.000 73.890 0.180 ;
    LAYER MET2 ;
    RECT 73.480 0.000 73.890 0.180 ;
    LAYER MET3 ;
    RECT 73.480 0.000 73.890 0.180 ;
  END
  ANTENNADIFFAREA                0.27730         LAYER MET1 ;
  ANTENNADIFFAREA                0.27730         LAYER MET2 ;
  ANTENNADIFFAREA                0.27730         LAYER MET3 ;
  ANTENNAGATEAREA                0.04200         LAYER MET1 ;
  ANTENNAGATEAREA                0.04200         LAYER MET2 ;
  ANTENNAGATEAREA                0.04200         LAYER MET3 ;
  ANTENNAPARTIALMETALAREA        0.11830         LAYER MET1 ;
  ANTENNAPARTIALMETALAREA        1.73460         LAYER MET2 ;
  ANTENNAPARTIALMETALAREA        0.36060         LAYER MET3 ;
  ANTENNAMAXAREACAR              1.54762         LAYER MET1 ;
  ANTENNAMAXAREACAR              6.99048         LAYER MET2 ;
  ANTENNAMAXAREACAR              15.57619        LAYER MET3 ;
END MARE
PIN MAR[0]
  DIRECTION INPUT ;
  PORT
    LAYER MET1 ;
    RECT 72.950 0.000 73.360 0.180 ;
    LAYER MET2 ;
    RECT 72.950 0.000 73.360 0.180 ;
    LAYER MET3 ;
    RECT 72.950 0.000 73.360 0.180 ;
  END
  ANTENNADIFFAREA                0.30530         LAYER MET1 ;
  ANTENNADIFFAREA                0.30530         LAYER MET2 ;
  ANTENNADIFFAREA                0.30530         LAYER MET3 ;
  ANTENNAGATEAREA                0.04200         LAYER MET1 ;
  ANTENNAGATEAREA                0.04200         LAYER MET2 ;
  ANTENNAGATEAREA                0.04200         LAYER MET3 ;
  ANTENNAPARTIALMETALAREA        0.40280         LAYER MET1 ;
  ANTENNAPARTIALMETALAREA        1.19340         LAYER MET2 ;
  ANTENNAMAXAREACAR              8.32143         LAYER MET1 ;
  ANTENNAMAXAREACAR              38.49286        LAYER MET2 ;
  ANTENNAMAXAREACAR              40.25000        LAYER MET3 ;
END MAR[0]
PIN MAR[1]
  DIRECTION INPUT ;
  PORT
    LAYER MET1 ;
    RECT 77.545 0.000 77.955 0.180 ;
    LAYER MET2 ;
    RECT 77.545 0.000 77.955 0.180 ;
    LAYER MET3 ;
    RECT 77.545 0.000 77.955 0.180 ;
  END
  ANTENNADIFFAREA                0.30530         LAYER MET1 ;
  ANTENNADIFFAREA                0.30530         LAYER MET2 ;
  ANTENNADIFFAREA                0.30530         LAYER MET3 ;
  ANTENNAGATEAREA                0.04200         LAYER MET1 ;
  ANTENNAGATEAREA                0.04200         LAYER MET2 ;
  ANTENNAGATEAREA                0.04200         LAYER MET3 ;
  ANTENNAPARTIALMETALAREA        0.29630         LAYER MET1 ;
  ANTENNAPARTIALMETALAREA        1.11780         LAYER MET2 ;
  ANTENNAMAXAREACAR              5.78571         LAYER MET1 ;
  ANTENNAMAXAREACAR              34.15714        LAYER MET2 ;
  ANTENNAMAXAREACAR              35.91429        LAYER MET3 ;
END MAR[1]
PIN MAR[2]
  DIRECTION INPUT ;
  PORT
    LAYER MET1 ;
    RECT 75.940 0.000 76.350 0.180 ;
    LAYER MET2 ;
    RECT 75.940 0.000 76.350 0.180 ;
    LAYER MET3 ;
    RECT 75.940 0.000 76.350 0.180 ;
  END
  ANTENNADIFFAREA                0.30530         LAYER MET1 ;
  ANTENNADIFFAREA                0.30530         LAYER MET2 ;
  ANTENNADIFFAREA                0.30530         LAYER MET3 ;
  ANTENNAGATEAREA                0.04200         LAYER MET1 ;
  ANTENNAGATEAREA                0.04200         LAYER MET2 ;
  ANTENNAGATEAREA                0.04200         LAYER MET3 ;
  ANTENNAPARTIALMETALAREA        0.12430         LAYER MET1 ;
  ANTENNAPARTIALMETALAREA        1.22700         LAYER MET2 ;
  ANTENNAMAXAREACAR              1.69048         LAYER MET1 ;
  ANTENNAMAXAREACAR              32.66190        LAYER MET2 ;
  ANTENNAMAXAREACAR              34.41905        LAYER MET3 ;
END MAR[2]
PIN MAR[3]
  DIRECTION INPUT ;
  PORT
    LAYER MET1 ;
    RECT 74.300 0.000 74.710 0.180 ;
    LAYER MET2 ;
    RECT 74.300 0.000 74.710 0.180 ;
    LAYER MET3 ;
    RECT 74.300 0.000 74.710 0.180 ;
  END
  ANTENNADIFFAREA                0.30530         LAYER MET1 ;
  ANTENNADIFFAREA                0.30530         LAYER MET2 ;
  ANTENNADIFFAREA                0.30530         LAYER MET3 ;
  ANTENNAGATEAREA                0.04200         LAYER MET1 ;
  ANTENNAGATEAREA                0.04200         LAYER MET2 ;
  ANTENNAGATEAREA                0.04200         LAYER MET3 ;
  ANTENNAPARTIALMETALAREA        0.32880         LAYER MET1 ;
  ANTENNAPARTIALMETALAREA        1.21620         LAYER MET2 ;
  ANTENNAMAXAREACAR              6.55952         LAYER MET1 ;
  ANTENNAMAXAREACAR              37.27381        LAYER MET2 ;
  ANTENNAMAXAREACAR              39.03095        LAYER MET3 ;
END MAR[3]
PIN A[0]
  DIRECTION INPUT ;
  PORT
    LAYER MET1 ;
    RECT 88.700 0.000 89.110 0.180 ;
    LAYER MET2 ;
    RECT 88.700 0.000 89.110 0.180 ;
    LAYER MET3 ;
    RECT 88.700 0.000 89.110 0.180 ;
  END
  ANTENNADIFFAREA                0.43130         LAYER MET1 ;
  ANTENNADIFFAREA                0.43130         LAYER MET2 ;
  ANTENNADIFFAREA                0.43130         LAYER MET3 ;
  ANTENNAGATEAREA                0.06300         LAYER MET1 ;
  ANTENNAGATEAREA                0.06300         LAYER MET2 ;
  ANTENNAGATEAREA                0.06300         LAYER MET3 ;
  ANTENNAPARTIALMETALAREA        0.11990         LAYER MET1 ;
  ANTENNAPARTIALMETALAREA        1.91700         LAYER MET2 ;
  ANTENNAMAXAREACAR              1.05714         LAYER MET1 ;
  ANTENNAMAXAREACAR              32.65714        LAYER MET2 ;
  ANTENNAMAXAREACAR              33.82857        LAYER MET3 ;
END A[0]
PIN A[1]
  DIRECTION INPUT ;
  PORT
    LAYER MET1 ;
    RECT 88.010 0.000 88.420 0.180 ;
    LAYER MET2 ;
    RECT 88.010 0.000 88.420 0.180 ;
    LAYER MET3 ;
    RECT 88.010 0.000 88.420 0.180 ;
  END
  ANTENNADIFFAREA                0.43130         LAYER MET1 ;
  ANTENNADIFFAREA                0.43130         LAYER MET2 ;
  ANTENNADIFFAREA                0.43130         LAYER MET3 ;
  ANTENNAGATEAREA                0.06300         LAYER MET1 ;
  ANTENNAGATEAREA                0.06300         LAYER MET2 ;
  ANTENNAGATEAREA                0.06300         LAYER MET3 ;
  ANTENNAPARTIALMETALAREA        0.09890         LAYER MET1 ;
  ANTENNAPARTIALMETALAREA        1.65700         LAYER MET2 ;
  ANTENNAMAXAREACAR              0.72381         LAYER MET1 ;
  ANTENNAMAXAREACAR              28.19683        LAYER MET2 ;
  ANTENNAMAXAREACAR              29.36825        LAYER MET3 ;
END A[1]
PIN A[2]
  DIRECTION INPUT ;
  PORT
    LAYER MET1 ;
    RECT 92.390 0.000 92.800 0.180 ;
    LAYER MET2 ;
    RECT 92.390 0.000 92.800 0.180 ;
    LAYER MET3 ;
    RECT 92.390 0.000 92.800 0.180 ;
  END
  ANTENNADIFFAREA                0.43130         LAYER MET1 ;
  ANTENNADIFFAREA                0.43130         LAYER MET2 ;
  ANTENNADIFFAREA                0.43130         LAYER MET3 ;
  ANTENNAGATEAREA                0.06300         LAYER MET1 ;
  ANTENNAGATEAREA                0.06300         LAYER MET2 ;
  ANTENNAGATEAREA                0.06300         LAYER MET3 ;
  ANTENNAPARTIALMETALAREA        0.11990         LAYER MET1 ;
  ANTENNAPARTIALMETALAREA        2.04550         LAYER MET2 ;
  ANTENNAMAXAREACAR              1.05714         LAYER MET1 ;
  ANTENNAMAXAREACAR              34.69683        LAYER MET2 ;
  ANTENNAMAXAREACAR              35.86825        LAYER MET3 ;
END A[2]
PIN A[3]
  DIRECTION INPUT ;
  PORT
    LAYER MET1 ;
    RECT 91.675 0.000 92.085 0.180 ;
    LAYER MET2 ;
    RECT 91.675 0.000 92.085 0.180 ;
    LAYER MET3 ;
    RECT 91.675 0.000 92.085 0.180 ;
  END
  ANTENNADIFFAREA                0.43130         LAYER MET1 ;
  ANTENNADIFFAREA                0.43130         LAYER MET2 ;
  ANTENNADIFFAREA                0.43130         LAYER MET3 ;
  ANTENNAGATEAREA                0.06300         LAYER MET1 ;
  ANTENNAGATEAREA                0.06300         LAYER MET2 ;
  ANTENNAGATEAREA                0.06300         LAYER MET3 ;
  ANTENNAPARTIALMETALAREA        0.09890         LAYER MET1 ;
  ANTENNAPARTIALMETALAREA        2.09300         LAYER MET2 ;
  ANTENNAMAXAREACAR              0.72381         LAYER MET1 ;
  ANTENNAMAXAREACAR              35.11746        LAYER MET2 ;
  ANTENNAMAXAREACAR              36.28889        LAYER MET3 ;
END A[3]
PIN A[4]
  DIRECTION INPUT ;
  PORT
    LAYER MET1 ;
    RECT 76.485 0.000 76.895 0.180 ;
    LAYER MET2 ;
    RECT 76.485 0.000 76.895 0.180 ;
    LAYER MET3 ;
    RECT 76.485 0.000 76.895 0.180 ;
  END
  ANTENNADIFFAREA                0.68330         LAYER MET1 ;
  ANTENNADIFFAREA                0.68330         LAYER MET2 ;
  ANTENNADIFFAREA                0.68330         LAYER MET3 ;
  ANTENNAGATEAREA                0.06300         LAYER MET1 ;
  ANTENNAGATEAREA                0.06300         LAYER MET2 ;
  ANTENNAGATEAREA                0.06300         LAYER MET3 ;
  ANTENNAPARTIALMETALAREA        0.09890         LAYER MET1 ;
  ANTENNAPARTIALMETALAREA        2.08200         LAYER MET2 ;
  ANTENNAMAXAREACAR              0.72381         LAYER MET1 ;
  ANTENNAMAXAREACAR              34.94286        LAYER MET2 ;
  ANTENNAMAXAREACAR              36.11429        LAYER MET3 ;
END A[4]
PIN A[5]
  DIRECTION INPUT ;
  PORT
    LAYER MET1 ;
    RECT 79.265 0.000 79.675 0.180 ;
    LAYER MET2 ;
    RECT 79.265 0.000 79.675 0.180 ;
    LAYER MET3 ;
    RECT 79.265 0.000 79.675 0.180 ;
  END
  ANTENNADIFFAREA                0.43130         LAYER MET1 ;
  ANTENNADIFFAREA                0.43130         LAYER MET2 ;
  ANTENNADIFFAREA                0.43130         LAYER MET3 ;
  ANTENNAGATEAREA                0.06300         LAYER MET1 ;
  ANTENNAGATEAREA                0.06300         LAYER MET2 ;
  ANTENNAGATEAREA                0.06300         LAYER MET3 ;
  ANTENNAPARTIALMETALAREA        0.17870         LAYER MET1 ;
  ANTENNAPARTIALMETALAREA        1.26000         LAYER MET2 ;
  ANTENNAMAXAREACAR              1.99048         LAYER MET1 ;
  ANTENNAMAXAREACAR              23.16190        LAYER MET2 ;
  ANTENNAMAXAREACAR              24.33333        LAYER MET3 ;
END A[5]
PIN A[6]
  DIRECTION INPUT ;
  PORT
    LAYER MET1 ;
    RECT 77.015 0.000 77.425 0.180 ;
    LAYER MET2 ;
    RECT 77.015 0.000 77.425 0.180 ;
    LAYER MET3 ;
    RECT 77.015 0.000 77.425 0.180 ;
  END
  ANTENNADIFFAREA                0.68330         LAYER MET1 ;
  ANTENNADIFFAREA                0.68330         LAYER MET2 ;
  ANTENNADIFFAREA                0.68330         LAYER MET3 ;
  ANTENNAGATEAREA                0.06300         LAYER MET1 ;
  ANTENNAGATEAREA                0.06300         LAYER MET2 ;
  ANTENNAGATEAREA                0.06300         LAYER MET3 ;
  ANTENNAPARTIALMETALAREA        0.09890         LAYER MET1 ;
  ANTENNAPARTIALMETALAREA        1.99560         LAYER MET2 ;
  ANTENNAMAXAREACAR              0.72381         LAYER MET1 ;
  ANTENNAMAXAREACAR              33.57143        LAYER MET2 ;
  ANTENNAMAXAREACAR              34.74286        LAYER MET3 ;
END A[6]
PIN A[7]
  DIRECTION INPUT ;
  PORT
    LAYER MET1 ;
    RECT 74.880 0.000 75.290 0.180 ;
    LAYER MET2 ;
    RECT 74.880 0.000 75.290 0.180 ;
    LAYER MET3 ;
    RECT 74.880 0.000 75.290 0.180 ;
  END
  ANTENNADIFFAREA                0.43130         LAYER MET1 ;
  ANTENNADIFFAREA                0.43130         LAYER MET2 ;
  ANTENNADIFFAREA                0.43130         LAYER MET3 ;
  ANTENNAGATEAREA                0.06300         LAYER MET1 ;
  ANTENNAGATEAREA                0.06300         LAYER MET2 ;
  ANTENNAGATEAREA                0.06300         LAYER MET3 ;
  ANTENNAPARTIALMETALAREA        0.14330         LAYER MET1 ;
  ANTENNAPARTIALMETALAREA        2.29080         LAYER MET2 ;
  ANTENNAMAXAREACAR              1.42857         LAYER MET1 ;
  ANTENNAMAXAREACAR              38.96190        LAYER MET2 ;
  ANTENNAMAXAREACAR              40.13333        LAYER MET3 ;
END A[7]
PIN A[8]
  DIRECTION INPUT ;
  PORT
    LAYER MET1 ;
    RECT 75.410 0.000 75.820 0.180 ;
    LAYER MET2 ;
    RECT 75.410 0.000 75.820 0.180 ;
    LAYER MET3 ;
    RECT 75.410 0.000 75.820 0.180 ;
  END
  ANTENNADIFFAREA                0.43130         LAYER MET1 ;
  ANTENNADIFFAREA                0.43130         LAYER MET2 ;
  ANTENNADIFFAREA                0.43130         LAYER MET3 ;
  ANTENNAGATEAREA                0.06300         LAYER MET1 ;
  ANTENNAGATEAREA                0.06300         LAYER MET2 ;
  ANTENNAGATEAREA                0.06300         LAYER MET3 ;
  ANTENNAPARTIALMETALAREA        0.09890         LAYER MET1 ;
  ANTENNAPARTIALMETALAREA        2.74740         LAYER MET2 ;
  ANTENNAMAXAREACAR              0.72381         LAYER MET1 ;
  ANTENNAMAXAREACAR              45.50476        LAYER MET2 ;
  ANTENNAMAXAREACAR              46.67619        LAYER MET3 ;
END A[8]
PIN D[16]
  DIRECTION INPUT ;
  PORT
    LAYER MET1 ;
    RECT 99.090 0.000 99.500 0.180 ;
    LAYER MET2 ;
    RECT 99.090 0.000 99.500 0.180 ;
    LAYER MET3 ;
    RECT 99.090 0.000 99.500 0.180 ;
  END
  ANTENNADIFFAREA                0.38930         LAYER MET1 ;
  ANTENNADIFFAREA                0.38930         LAYER MET2 ;
  ANTENNADIFFAREA                0.38930         LAYER MET3 ;
  ANTENNAGATEAREA                0.06300         LAYER MET1 ;
  ANTENNAGATEAREA                0.06300         LAYER MET2 ;
  ANTENNAGATEAREA                0.06300         LAYER MET3 ;
  ANTENNAPARTIALMETALAREA        0.09890         LAYER MET1 ;
  ANTENNAPARTIALMETALAREA        0.10380         LAYER MET2 ;
  ANTENNAMAXAREACAR              0.72381         LAYER MET1 ;
  ANTENNAMAXAREACAR              3.54286         LAYER MET2 ;
  ANTENNAMAXAREACAR              4.71429         LAYER MET3 ;
END D[16]
PIN Q[16]
  DIRECTION OUTPUT ;
  PORT
    LAYER MET1 ;
    RECT 97.550 0.000 97.960 0.180 ;
    LAYER MET2 ;
    RECT 97.550 0.000 97.960 0.180 ;
    LAYER MET3 ;
    RECT 97.550 0.000 97.960 0.180 ;
  END
  ANTENNADIFFAREA                0.60000         LAYER MET1 ;
  ANTENNADIFFAREA                0.60000         LAYER MET2 ;
  ANTENNADIFFAREA                0.60000         LAYER MET3 ;
  ANTENNAPARTIALMETALAREA        0.94400         LAYER MET1 ;
  ANTENNAPARTIALMETALAREA        1.33320         LAYER MET2 ;
END Q[16]
PIN WEB[16]
  DIRECTION INPUT ;
  PORT
    LAYER MET1 ;
    RECT 96.740 0.000 97.150 0.180 ;
    LAYER MET2 ;
    RECT 96.740 0.000 97.150 0.180 ;
    LAYER MET3 ;
    RECT 96.740 0.000 97.150 0.180 ;
  END
  ANTENNADIFFAREA                0.45930         LAYER MET1 ;
  ANTENNADIFFAREA                0.45930         LAYER MET2 ;
  ANTENNADIFFAREA                0.45930         LAYER MET3 ;
  ANTENNAGATEAREA                0.08100         LAYER MET1 ;
  ANTENNAGATEAREA                0.08100         LAYER MET2 ;
  ANTENNAGATEAREA                0.08100         LAYER MET3 ;
  ANTENNAPARTIALMETALAREA        0.14210         LAYER MET1 ;
  ANTENNAPARTIALMETALAREA        0.09360         LAYER MET2 ;
  ANTENNAMAXAREACAR              1.09630         LAYER MET1 ;
  ANTENNAMAXAREACAR              3.16296         LAYER MET2 ;
  ANTENNAMAXAREACAR              4.07407         LAYER MET3 ;
END WEB[16]
PIN D[17]
  DIRECTION INPUT ;
  PORT
    LAYER MET1 ;
    RECT 103.290 0.000 103.700 0.180 ;
    LAYER MET2 ;
    RECT 103.290 0.000 103.700 0.180 ;
    LAYER MET3 ;
    RECT 103.290 0.000 103.700 0.180 ;
  END
  ANTENNADIFFAREA                0.38930         LAYER MET1 ;
  ANTENNADIFFAREA                0.38930         LAYER MET2 ;
  ANTENNADIFFAREA                0.38930         LAYER MET3 ;
  ANTENNAGATEAREA                0.06300         LAYER MET1 ;
  ANTENNAGATEAREA                0.06300         LAYER MET2 ;
  ANTENNAGATEAREA                0.06300         LAYER MET3 ;
  ANTENNAPARTIALMETALAREA        0.09890         LAYER MET1 ;
  ANTENNAPARTIALMETALAREA        0.10380         LAYER MET2 ;
  ANTENNAMAXAREACAR              0.72381         LAYER MET1 ;
  ANTENNAMAXAREACAR              3.54286         LAYER MET2 ;
  ANTENNAMAXAREACAR              4.71429         LAYER MET3 ;
END D[17]
PIN Q[17]
  DIRECTION OUTPUT ;
  PORT
    LAYER MET1 ;
    RECT 101.750 0.000 102.160 0.180 ;
    LAYER MET2 ;
    RECT 101.750 0.000 102.160 0.180 ;
    LAYER MET3 ;
    RECT 101.750 0.000 102.160 0.180 ;
  END
  ANTENNADIFFAREA                0.60000         LAYER MET1 ;
  ANTENNADIFFAREA                0.60000         LAYER MET2 ;
  ANTENNADIFFAREA                0.60000         LAYER MET3 ;
  ANTENNAPARTIALMETALAREA        0.94400         LAYER MET1 ;
  ANTENNAPARTIALMETALAREA        1.33320         LAYER MET2 ;
END Q[17]
PIN WEB[17]
  DIRECTION INPUT ;
  PORT
    LAYER MET1 ;
    RECT 100.940 0.000 101.350 0.180 ;
    LAYER MET2 ;
    RECT 100.940 0.000 101.350 0.180 ;
    LAYER MET3 ;
    RECT 100.940 0.000 101.350 0.180 ;
  END
  ANTENNADIFFAREA                0.45930         LAYER MET1 ;
  ANTENNADIFFAREA                0.45930         LAYER MET2 ;
  ANTENNADIFFAREA                0.45930         LAYER MET3 ;
  ANTENNAGATEAREA                0.08100         LAYER MET1 ;
  ANTENNAGATEAREA                0.08100         LAYER MET2 ;
  ANTENNAGATEAREA                0.08100         LAYER MET3 ;
  ANTENNAPARTIALMETALAREA        0.14210         LAYER MET1 ;
  ANTENNAPARTIALMETALAREA        0.09360         LAYER MET2 ;
  ANTENNAMAXAREACAR              1.09630         LAYER MET1 ;
  ANTENNAMAXAREACAR              3.16296         LAYER MET2 ;
  ANTENNAMAXAREACAR              4.07407         LAYER MET3 ;
END WEB[17]
PIN D[18]
  DIRECTION INPUT ;
  PORT
    LAYER MET1 ;
    RECT 107.490 0.000 107.900 0.180 ;
    LAYER MET2 ;
    RECT 107.490 0.000 107.900 0.180 ;
    LAYER MET3 ;
    RECT 107.490 0.000 107.900 0.180 ;
  END
  ANTENNADIFFAREA                0.38930         LAYER MET1 ;
  ANTENNADIFFAREA                0.38930         LAYER MET2 ;
  ANTENNADIFFAREA                0.38930         LAYER MET3 ;
  ANTENNAGATEAREA                0.06300         LAYER MET1 ;
  ANTENNAGATEAREA                0.06300         LAYER MET2 ;
  ANTENNAGATEAREA                0.06300         LAYER MET3 ;
  ANTENNAPARTIALMETALAREA        0.09890         LAYER MET1 ;
  ANTENNAPARTIALMETALAREA        0.10380         LAYER MET2 ;
  ANTENNAMAXAREACAR              0.72381         LAYER MET1 ;
  ANTENNAMAXAREACAR              3.54286         LAYER MET2 ;
  ANTENNAMAXAREACAR              4.71429         LAYER MET3 ;
END D[18]
PIN Q[18]
  DIRECTION OUTPUT ;
  PORT
    LAYER MET1 ;
    RECT 105.950 0.000 106.360 0.180 ;
    LAYER MET2 ;
    RECT 105.950 0.000 106.360 0.180 ;
    LAYER MET3 ;
    RECT 105.950 0.000 106.360 0.180 ;
  END
  ANTENNADIFFAREA                0.60000         LAYER MET1 ;
  ANTENNADIFFAREA                0.60000         LAYER MET2 ;
  ANTENNADIFFAREA                0.60000         LAYER MET3 ;
  ANTENNAPARTIALMETALAREA        0.94400         LAYER MET1 ;
  ANTENNAPARTIALMETALAREA        1.33320         LAYER MET2 ;
END Q[18]
PIN WEB[18]
  DIRECTION INPUT ;
  PORT
    LAYER MET1 ;
    RECT 105.140 0.000 105.550 0.180 ;
    LAYER MET2 ;
    RECT 105.140 0.000 105.550 0.180 ;
    LAYER MET3 ;
    RECT 105.140 0.000 105.550 0.180 ;
  END
  ANTENNADIFFAREA                0.45930         LAYER MET1 ;
  ANTENNADIFFAREA                0.45930         LAYER MET2 ;
  ANTENNADIFFAREA                0.45930         LAYER MET3 ;
  ANTENNAGATEAREA                0.08100         LAYER MET1 ;
  ANTENNAGATEAREA                0.08100         LAYER MET2 ;
  ANTENNAGATEAREA                0.08100         LAYER MET3 ;
  ANTENNAPARTIALMETALAREA        0.14210         LAYER MET1 ;
  ANTENNAPARTIALMETALAREA        0.09360         LAYER MET2 ;
  ANTENNAMAXAREACAR              1.09630         LAYER MET1 ;
  ANTENNAMAXAREACAR              3.16296         LAYER MET2 ;
  ANTENNAMAXAREACAR              4.07407         LAYER MET3 ;
END WEB[18]
PIN D[19]
  DIRECTION INPUT ;
  PORT
    LAYER MET1 ;
    RECT 111.690 0.000 112.100 0.180 ;
    LAYER MET2 ;
    RECT 111.690 0.000 112.100 0.180 ;
    LAYER MET3 ;
    RECT 111.690 0.000 112.100 0.180 ;
  END
  ANTENNADIFFAREA                0.38930         LAYER MET1 ;
  ANTENNADIFFAREA                0.38930         LAYER MET2 ;
  ANTENNADIFFAREA                0.38930         LAYER MET3 ;
  ANTENNAGATEAREA                0.06300         LAYER MET1 ;
  ANTENNAGATEAREA                0.06300         LAYER MET2 ;
  ANTENNAGATEAREA                0.06300         LAYER MET3 ;
  ANTENNAPARTIALMETALAREA        0.09890         LAYER MET1 ;
  ANTENNAPARTIALMETALAREA        0.10380         LAYER MET2 ;
  ANTENNAMAXAREACAR              0.72381         LAYER MET1 ;
  ANTENNAMAXAREACAR              3.54286         LAYER MET2 ;
  ANTENNAMAXAREACAR              4.71429         LAYER MET3 ;
END D[19]
PIN Q[19]
  DIRECTION OUTPUT ;
  PORT
    LAYER MET1 ;
    RECT 110.150 0.000 110.560 0.180 ;
    LAYER MET2 ;
    RECT 110.150 0.000 110.560 0.180 ;
    LAYER MET3 ;
    RECT 110.150 0.000 110.560 0.180 ;
  END
  ANTENNADIFFAREA                0.60000         LAYER MET1 ;
  ANTENNADIFFAREA                0.60000         LAYER MET2 ;
  ANTENNADIFFAREA                0.60000         LAYER MET3 ;
  ANTENNAPARTIALMETALAREA        0.94400         LAYER MET1 ;
  ANTENNAPARTIALMETALAREA        1.33320         LAYER MET2 ;
END Q[19]
PIN WEB[19]
  DIRECTION INPUT ;
  PORT
    LAYER MET1 ;
    RECT 109.340 0.000 109.750 0.180 ;
    LAYER MET2 ;
    RECT 109.340 0.000 109.750 0.180 ;
    LAYER MET3 ;
    RECT 109.340 0.000 109.750 0.180 ;
  END
  ANTENNADIFFAREA                0.45930         LAYER MET1 ;
  ANTENNADIFFAREA                0.45930         LAYER MET2 ;
  ANTENNADIFFAREA                0.45930         LAYER MET3 ;
  ANTENNAGATEAREA                0.08100         LAYER MET1 ;
  ANTENNAGATEAREA                0.08100         LAYER MET2 ;
  ANTENNAGATEAREA                0.08100         LAYER MET3 ;
  ANTENNAPARTIALMETALAREA        0.14210         LAYER MET1 ;
  ANTENNAPARTIALMETALAREA        0.09360         LAYER MET2 ;
  ANTENNAMAXAREACAR              1.09630         LAYER MET1 ;
  ANTENNAMAXAREACAR              3.16296         LAYER MET2 ;
  ANTENNAMAXAREACAR              4.07407         LAYER MET3 ;
END WEB[19]
PIN D[20]
  DIRECTION INPUT ;
  PORT
    LAYER MET1 ;
    RECT 115.890 0.000 116.300 0.180 ;
    LAYER MET2 ;
    RECT 115.890 0.000 116.300 0.180 ;
    LAYER MET3 ;
    RECT 115.890 0.000 116.300 0.180 ;
  END
  ANTENNADIFFAREA                0.38930         LAYER MET1 ;
  ANTENNADIFFAREA                0.38930         LAYER MET2 ;
  ANTENNADIFFAREA                0.38930         LAYER MET3 ;
  ANTENNAGATEAREA                0.06300         LAYER MET1 ;
  ANTENNAGATEAREA                0.06300         LAYER MET2 ;
  ANTENNAGATEAREA                0.06300         LAYER MET3 ;
  ANTENNAPARTIALMETALAREA        0.09890         LAYER MET1 ;
  ANTENNAPARTIALMETALAREA        0.10380         LAYER MET2 ;
  ANTENNAMAXAREACAR              0.72381         LAYER MET1 ;
  ANTENNAMAXAREACAR              3.54286         LAYER MET2 ;
  ANTENNAMAXAREACAR              4.71429         LAYER MET3 ;
END D[20]
PIN Q[20]
  DIRECTION OUTPUT ;
  PORT
    LAYER MET1 ;
    RECT 114.350 0.000 114.760 0.180 ;
    LAYER MET2 ;
    RECT 114.350 0.000 114.760 0.180 ;
    LAYER MET3 ;
    RECT 114.350 0.000 114.760 0.180 ;
  END
  ANTENNADIFFAREA                0.60000         LAYER MET1 ;
  ANTENNADIFFAREA                0.60000         LAYER MET2 ;
  ANTENNADIFFAREA                0.60000         LAYER MET3 ;
  ANTENNAPARTIALMETALAREA        0.94400         LAYER MET1 ;
  ANTENNAPARTIALMETALAREA        1.33320         LAYER MET2 ;
END Q[20]
PIN WEB[20]
  DIRECTION INPUT ;
  PORT
    LAYER MET1 ;
    RECT 113.540 0.000 113.950 0.180 ;
    LAYER MET2 ;
    RECT 113.540 0.000 113.950 0.180 ;
    LAYER MET3 ;
    RECT 113.540 0.000 113.950 0.180 ;
  END
  ANTENNADIFFAREA                0.45930         LAYER MET1 ;
  ANTENNADIFFAREA                0.45930         LAYER MET2 ;
  ANTENNADIFFAREA                0.45930         LAYER MET3 ;
  ANTENNAGATEAREA                0.08100         LAYER MET1 ;
  ANTENNAGATEAREA                0.08100         LAYER MET2 ;
  ANTENNAGATEAREA                0.08100         LAYER MET3 ;
  ANTENNAPARTIALMETALAREA        0.14210         LAYER MET1 ;
  ANTENNAPARTIALMETALAREA        0.09360         LAYER MET2 ;
  ANTENNAMAXAREACAR              1.09630         LAYER MET1 ;
  ANTENNAMAXAREACAR              3.16296         LAYER MET2 ;
  ANTENNAMAXAREACAR              4.07407         LAYER MET3 ;
END WEB[20]
PIN D[21]
  DIRECTION INPUT ;
  PORT
    LAYER MET1 ;
    RECT 120.090 0.000 120.500 0.180 ;
    LAYER MET2 ;
    RECT 120.090 0.000 120.500 0.180 ;
    LAYER MET3 ;
    RECT 120.090 0.000 120.500 0.180 ;
  END
  ANTENNADIFFAREA                0.38930         LAYER MET1 ;
  ANTENNADIFFAREA                0.38930         LAYER MET2 ;
  ANTENNADIFFAREA                0.38930         LAYER MET3 ;
  ANTENNAGATEAREA                0.06300         LAYER MET1 ;
  ANTENNAGATEAREA                0.06300         LAYER MET2 ;
  ANTENNAGATEAREA                0.06300         LAYER MET3 ;
  ANTENNAPARTIALMETALAREA        0.09890         LAYER MET1 ;
  ANTENNAPARTIALMETALAREA        0.10380         LAYER MET2 ;
  ANTENNAMAXAREACAR              0.72381         LAYER MET1 ;
  ANTENNAMAXAREACAR              3.54286         LAYER MET2 ;
  ANTENNAMAXAREACAR              4.71429         LAYER MET3 ;
END D[21]
PIN Q[21]
  DIRECTION OUTPUT ;
  PORT
    LAYER MET1 ;
    RECT 118.550 0.000 118.960 0.180 ;
    LAYER MET2 ;
    RECT 118.550 0.000 118.960 0.180 ;
    LAYER MET3 ;
    RECT 118.550 0.000 118.960 0.180 ;
  END
  ANTENNADIFFAREA                0.60000         LAYER MET1 ;
  ANTENNADIFFAREA                0.60000         LAYER MET2 ;
  ANTENNADIFFAREA                0.60000         LAYER MET3 ;
  ANTENNAPARTIALMETALAREA        0.94400         LAYER MET1 ;
  ANTENNAPARTIALMETALAREA        1.33320         LAYER MET2 ;
END Q[21]
PIN WEB[21]
  DIRECTION INPUT ;
  PORT
    LAYER MET1 ;
    RECT 117.740 0.000 118.150 0.180 ;
    LAYER MET2 ;
    RECT 117.740 0.000 118.150 0.180 ;
    LAYER MET3 ;
    RECT 117.740 0.000 118.150 0.180 ;
  END
  ANTENNADIFFAREA                0.45930         LAYER MET1 ;
  ANTENNADIFFAREA                0.45930         LAYER MET2 ;
  ANTENNADIFFAREA                0.45930         LAYER MET3 ;
  ANTENNAGATEAREA                0.08100         LAYER MET1 ;
  ANTENNAGATEAREA                0.08100         LAYER MET2 ;
  ANTENNAGATEAREA                0.08100         LAYER MET3 ;
  ANTENNAPARTIALMETALAREA        0.14210         LAYER MET1 ;
  ANTENNAPARTIALMETALAREA        0.09360         LAYER MET2 ;
  ANTENNAMAXAREACAR              1.09630         LAYER MET1 ;
  ANTENNAMAXAREACAR              3.16296         LAYER MET2 ;
  ANTENNAMAXAREACAR              4.07407         LAYER MET3 ;
END WEB[21]
PIN D[22]
  DIRECTION INPUT ;
  PORT
    LAYER MET1 ;
    RECT 124.290 0.000 124.700 0.180 ;
    LAYER MET2 ;
    RECT 124.290 0.000 124.700 0.180 ;
    LAYER MET3 ;
    RECT 124.290 0.000 124.700 0.180 ;
  END
  ANTENNADIFFAREA                0.38930         LAYER MET1 ;
  ANTENNADIFFAREA                0.38930         LAYER MET2 ;
  ANTENNADIFFAREA                0.38930         LAYER MET3 ;
  ANTENNAGATEAREA                0.06300         LAYER MET1 ;
  ANTENNAGATEAREA                0.06300         LAYER MET2 ;
  ANTENNAGATEAREA                0.06300         LAYER MET3 ;
  ANTENNAPARTIALMETALAREA        0.09890         LAYER MET1 ;
  ANTENNAPARTIALMETALAREA        0.10380         LAYER MET2 ;
  ANTENNAMAXAREACAR              0.72381         LAYER MET1 ;
  ANTENNAMAXAREACAR              3.54286         LAYER MET2 ;
  ANTENNAMAXAREACAR              4.71429         LAYER MET3 ;
END D[22]
PIN Q[22]
  DIRECTION OUTPUT ;
  PORT
    LAYER MET1 ;
    RECT 122.750 0.000 123.160 0.180 ;
    LAYER MET2 ;
    RECT 122.750 0.000 123.160 0.180 ;
    LAYER MET3 ;
    RECT 122.750 0.000 123.160 0.180 ;
  END
  ANTENNADIFFAREA                0.60000         LAYER MET1 ;
  ANTENNADIFFAREA                0.60000         LAYER MET2 ;
  ANTENNADIFFAREA                0.60000         LAYER MET3 ;
  ANTENNAPARTIALMETALAREA        0.94400         LAYER MET1 ;
  ANTENNAPARTIALMETALAREA        1.33320         LAYER MET2 ;
END Q[22]
PIN WEB[22]
  DIRECTION INPUT ;
  PORT
    LAYER MET1 ;
    RECT 121.940 0.000 122.350 0.180 ;
    LAYER MET2 ;
    RECT 121.940 0.000 122.350 0.180 ;
    LAYER MET3 ;
    RECT 121.940 0.000 122.350 0.180 ;
  END
  ANTENNADIFFAREA                0.45930         LAYER MET1 ;
  ANTENNADIFFAREA                0.45930         LAYER MET2 ;
  ANTENNADIFFAREA                0.45930         LAYER MET3 ;
  ANTENNAGATEAREA                0.08100         LAYER MET1 ;
  ANTENNAGATEAREA                0.08100         LAYER MET2 ;
  ANTENNAGATEAREA                0.08100         LAYER MET3 ;
  ANTENNAPARTIALMETALAREA        0.14210         LAYER MET1 ;
  ANTENNAPARTIALMETALAREA        0.09360         LAYER MET2 ;
  ANTENNAMAXAREACAR              1.09630         LAYER MET1 ;
  ANTENNAMAXAREACAR              3.16296         LAYER MET2 ;
  ANTENNAMAXAREACAR              4.07407         LAYER MET3 ;
END WEB[22]
PIN D[23]
  DIRECTION INPUT ;
  PORT
    LAYER MET1 ;
    RECT 128.490 0.000 128.900 0.180 ;
    LAYER MET2 ;
    RECT 128.490 0.000 128.900 0.180 ;
    LAYER MET3 ;
    RECT 128.490 0.000 128.900 0.180 ;
  END
  ANTENNADIFFAREA                0.38930         LAYER MET1 ;
  ANTENNADIFFAREA                0.38930         LAYER MET2 ;
  ANTENNADIFFAREA                0.38930         LAYER MET3 ;
  ANTENNAGATEAREA                0.06300         LAYER MET1 ;
  ANTENNAGATEAREA                0.06300         LAYER MET2 ;
  ANTENNAGATEAREA                0.06300         LAYER MET3 ;
  ANTENNAPARTIALMETALAREA        0.09890         LAYER MET1 ;
  ANTENNAPARTIALMETALAREA        0.10380         LAYER MET2 ;
  ANTENNAMAXAREACAR              0.72381         LAYER MET1 ;
  ANTENNAMAXAREACAR              3.54286         LAYER MET2 ;
  ANTENNAMAXAREACAR              4.71429         LAYER MET3 ;
END D[23]
PIN Q[23]
  DIRECTION OUTPUT ;
  PORT
    LAYER MET1 ;
    RECT 126.950 0.000 127.360 0.180 ;
    LAYER MET2 ;
    RECT 126.950 0.000 127.360 0.180 ;
    LAYER MET3 ;
    RECT 126.950 0.000 127.360 0.180 ;
  END
  ANTENNADIFFAREA                0.60000         LAYER MET1 ;
  ANTENNADIFFAREA                0.60000         LAYER MET2 ;
  ANTENNADIFFAREA                0.60000         LAYER MET3 ;
  ANTENNAPARTIALMETALAREA        0.94400         LAYER MET1 ;
  ANTENNAPARTIALMETALAREA        1.33320         LAYER MET2 ;
END Q[23]
PIN WEB[23]
  DIRECTION INPUT ;
  PORT
    LAYER MET1 ;
    RECT 126.140 0.000 126.550 0.180 ;
    LAYER MET2 ;
    RECT 126.140 0.000 126.550 0.180 ;
    LAYER MET3 ;
    RECT 126.140 0.000 126.550 0.180 ;
  END
  ANTENNADIFFAREA                0.45930         LAYER MET1 ;
  ANTENNADIFFAREA                0.45930         LAYER MET2 ;
  ANTENNADIFFAREA                0.45930         LAYER MET3 ;
  ANTENNAGATEAREA                0.08100         LAYER MET1 ;
  ANTENNAGATEAREA                0.08100         LAYER MET2 ;
  ANTENNAGATEAREA                0.08100         LAYER MET3 ;
  ANTENNAPARTIALMETALAREA        0.14210         LAYER MET1 ;
  ANTENNAPARTIALMETALAREA        0.09360         LAYER MET2 ;
  ANTENNAMAXAREACAR              1.09630         LAYER MET1 ;
  ANTENNAMAXAREACAR              3.16296         LAYER MET2 ;
  ANTENNAMAXAREACAR              4.07407         LAYER MET3 ;
END WEB[23]
PIN D[24]
  DIRECTION INPUT ;
  PORT
    LAYER MET1 ;
    RECT 132.690 0.000 133.100 0.180 ;
    LAYER MET2 ;
    RECT 132.690 0.000 133.100 0.180 ;
    LAYER MET3 ;
    RECT 132.690 0.000 133.100 0.180 ;
  END
  ANTENNADIFFAREA                0.38930         LAYER MET1 ;
  ANTENNADIFFAREA                0.38930         LAYER MET2 ;
  ANTENNADIFFAREA                0.38930         LAYER MET3 ;
  ANTENNAGATEAREA                0.06300         LAYER MET1 ;
  ANTENNAGATEAREA                0.06300         LAYER MET2 ;
  ANTENNAGATEAREA                0.06300         LAYER MET3 ;
  ANTENNAPARTIALMETALAREA        0.09890         LAYER MET1 ;
  ANTENNAPARTIALMETALAREA        0.10380         LAYER MET2 ;
  ANTENNAMAXAREACAR              0.72381         LAYER MET1 ;
  ANTENNAMAXAREACAR              3.54286         LAYER MET2 ;
  ANTENNAMAXAREACAR              4.71429         LAYER MET3 ;
END D[24]
PIN Q[24]
  DIRECTION OUTPUT ;
  PORT
    LAYER MET1 ;
    RECT 131.150 0.000 131.560 0.180 ;
    LAYER MET2 ;
    RECT 131.150 0.000 131.560 0.180 ;
    LAYER MET3 ;
    RECT 131.150 0.000 131.560 0.180 ;
  END
  ANTENNADIFFAREA                0.60000         LAYER MET1 ;
  ANTENNADIFFAREA                0.60000         LAYER MET2 ;
  ANTENNADIFFAREA                0.60000         LAYER MET3 ;
  ANTENNAPARTIALMETALAREA        0.94400         LAYER MET1 ;
  ANTENNAPARTIALMETALAREA        1.33320         LAYER MET2 ;
END Q[24]
PIN WEB[24]
  DIRECTION INPUT ;
  PORT
    LAYER MET1 ;
    RECT 130.340 0.000 130.750 0.180 ;
    LAYER MET2 ;
    RECT 130.340 0.000 130.750 0.180 ;
    LAYER MET3 ;
    RECT 130.340 0.000 130.750 0.180 ;
  END
  ANTENNADIFFAREA                0.45930         LAYER MET1 ;
  ANTENNADIFFAREA                0.45930         LAYER MET2 ;
  ANTENNADIFFAREA                0.45930         LAYER MET3 ;
  ANTENNAGATEAREA                0.08100         LAYER MET1 ;
  ANTENNAGATEAREA                0.08100         LAYER MET2 ;
  ANTENNAGATEAREA                0.08100         LAYER MET3 ;
  ANTENNAPARTIALMETALAREA        0.14210         LAYER MET1 ;
  ANTENNAPARTIALMETALAREA        0.09360         LAYER MET2 ;
  ANTENNAMAXAREACAR              1.09630         LAYER MET1 ;
  ANTENNAMAXAREACAR              3.16296         LAYER MET2 ;
  ANTENNAMAXAREACAR              4.07407         LAYER MET3 ;
END WEB[24]
PIN D[25]
  DIRECTION INPUT ;
  PORT
    LAYER MET1 ;
    RECT 136.890 0.000 137.300 0.180 ;
    LAYER MET2 ;
    RECT 136.890 0.000 137.300 0.180 ;
    LAYER MET3 ;
    RECT 136.890 0.000 137.300 0.180 ;
  END
  ANTENNADIFFAREA                0.38930         LAYER MET1 ;
  ANTENNADIFFAREA                0.38930         LAYER MET2 ;
  ANTENNADIFFAREA                0.38930         LAYER MET3 ;
  ANTENNAGATEAREA                0.06300         LAYER MET1 ;
  ANTENNAGATEAREA                0.06300         LAYER MET2 ;
  ANTENNAGATEAREA                0.06300         LAYER MET3 ;
  ANTENNAPARTIALMETALAREA        0.09890         LAYER MET1 ;
  ANTENNAPARTIALMETALAREA        0.10380         LAYER MET2 ;
  ANTENNAMAXAREACAR              0.72381         LAYER MET1 ;
  ANTENNAMAXAREACAR              3.54286         LAYER MET2 ;
  ANTENNAMAXAREACAR              4.71429         LAYER MET3 ;
END D[25]
PIN Q[25]
  DIRECTION OUTPUT ;
  PORT
    LAYER MET1 ;
    RECT 135.350 0.000 135.760 0.180 ;
    LAYER MET2 ;
    RECT 135.350 0.000 135.760 0.180 ;
    LAYER MET3 ;
    RECT 135.350 0.000 135.760 0.180 ;
  END
  ANTENNADIFFAREA                0.60000         LAYER MET1 ;
  ANTENNADIFFAREA                0.60000         LAYER MET2 ;
  ANTENNADIFFAREA                0.60000         LAYER MET3 ;
  ANTENNAPARTIALMETALAREA        0.94400         LAYER MET1 ;
  ANTENNAPARTIALMETALAREA        1.33320         LAYER MET2 ;
END Q[25]
PIN WEB[25]
  DIRECTION INPUT ;
  PORT
    LAYER MET1 ;
    RECT 134.540 0.000 134.950 0.180 ;
    LAYER MET2 ;
    RECT 134.540 0.000 134.950 0.180 ;
    LAYER MET3 ;
    RECT 134.540 0.000 134.950 0.180 ;
  END
  ANTENNADIFFAREA                0.45930         LAYER MET1 ;
  ANTENNADIFFAREA                0.45930         LAYER MET2 ;
  ANTENNADIFFAREA                0.45930         LAYER MET3 ;
  ANTENNAGATEAREA                0.08100         LAYER MET1 ;
  ANTENNAGATEAREA                0.08100         LAYER MET2 ;
  ANTENNAGATEAREA                0.08100         LAYER MET3 ;
  ANTENNAPARTIALMETALAREA        0.14210         LAYER MET1 ;
  ANTENNAPARTIALMETALAREA        0.09360         LAYER MET2 ;
  ANTENNAMAXAREACAR              1.09630         LAYER MET1 ;
  ANTENNAMAXAREACAR              3.16296         LAYER MET2 ;
  ANTENNAMAXAREACAR              4.07407         LAYER MET3 ;
END WEB[25]
PIN D[26]
  DIRECTION INPUT ;
  PORT
    LAYER MET1 ;
    RECT 141.090 0.000 141.500 0.180 ;
    LAYER MET2 ;
    RECT 141.090 0.000 141.500 0.180 ;
    LAYER MET3 ;
    RECT 141.090 0.000 141.500 0.180 ;
  END
  ANTENNADIFFAREA                0.38930         LAYER MET1 ;
  ANTENNADIFFAREA                0.38930         LAYER MET2 ;
  ANTENNADIFFAREA                0.38930         LAYER MET3 ;
  ANTENNAGATEAREA                0.06300         LAYER MET1 ;
  ANTENNAGATEAREA                0.06300         LAYER MET2 ;
  ANTENNAGATEAREA                0.06300         LAYER MET3 ;
  ANTENNAPARTIALMETALAREA        0.09890         LAYER MET1 ;
  ANTENNAPARTIALMETALAREA        0.10380         LAYER MET2 ;
  ANTENNAMAXAREACAR              0.72381         LAYER MET1 ;
  ANTENNAMAXAREACAR              3.54286         LAYER MET2 ;
  ANTENNAMAXAREACAR              4.71429         LAYER MET3 ;
END D[26]
PIN Q[26]
  DIRECTION OUTPUT ;
  PORT
    LAYER MET1 ;
    RECT 139.550 0.000 139.960 0.180 ;
    LAYER MET2 ;
    RECT 139.550 0.000 139.960 0.180 ;
    LAYER MET3 ;
    RECT 139.550 0.000 139.960 0.180 ;
  END
  ANTENNADIFFAREA                0.60000         LAYER MET1 ;
  ANTENNADIFFAREA                0.60000         LAYER MET2 ;
  ANTENNADIFFAREA                0.60000         LAYER MET3 ;
  ANTENNAPARTIALMETALAREA        0.94400         LAYER MET1 ;
  ANTENNAPARTIALMETALAREA        1.33320         LAYER MET2 ;
END Q[26]
PIN WEB[26]
  DIRECTION INPUT ;
  PORT
    LAYER MET1 ;
    RECT 138.740 0.000 139.150 0.180 ;
    LAYER MET2 ;
    RECT 138.740 0.000 139.150 0.180 ;
    LAYER MET3 ;
    RECT 138.740 0.000 139.150 0.180 ;
  END
  ANTENNADIFFAREA                0.45930         LAYER MET1 ;
  ANTENNADIFFAREA                0.45930         LAYER MET2 ;
  ANTENNADIFFAREA                0.45930         LAYER MET3 ;
  ANTENNAGATEAREA                0.08100         LAYER MET1 ;
  ANTENNAGATEAREA                0.08100         LAYER MET2 ;
  ANTENNAGATEAREA                0.08100         LAYER MET3 ;
  ANTENNAPARTIALMETALAREA        0.14210         LAYER MET1 ;
  ANTENNAPARTIALMETALAREA        0.09360         LAYER MET2 ;
  ANTENNAMAXAREACAR              1.09630         LAYER MET1 ;
  ANTENNAMAXAREACAR              3.16296         LAYER MET2 ;
  ANTENNAMAXAREACAR              4.07407         LAYER MET3 ;
END WEB[26]
PIN D[27]
  DIRECTION INPUT ;
  PORT
    LAYER MET1 ;
    RECT 145.290 0.000 145.700 0.180 ;
    LAYER MET2 ;
    RECT 145.290 0.000 145.700 0.180 ;
    LAYER MET3 ;
    RECT 145.290 0.000 145.700 0.180 ;
  END
  ANTENNADIFFAREA                0.38930         LAYER MET1 ;
  ANTENNADIFFAREA                0.38930         LAYER MET2 ;
  ANTENNADIFFAREA                0.38930         LAYER MET3 ;
  ANTENNAGATEAREA                0.06300         LAYER MET1 ;
  ANTENNAGATEAREA                0.06300         LAYER MET2 ;
  ANTENNAGATEAREA                0.06300         LAYER MET3 ;
  ANTENNAPARTIALMETALAREA        0.09890         LAYER MET1 ;
  ANTENNAPARTIALMETALAREA        0.10380         LAYER MET2 ;
  ANTENNAMAXAREACAR              0.72381         LAYER MET1 ;
  ANTENNAMAXAREACAR              3.54286         LAYER MET2 ;
  ANTENNAMAXAREACAR              4.71429         LAYER MET3 ;
END D[27]
PIN Q[27]
  DIRECTION OUTPUT ;
  PORT
    LAYER MET1 ;
    RECT 143.750 0.000 144.160 0.180 ;
    LAYER MET2 ;
    RECT 143.750 0.000 144.160 0.180 ;
    LAYER MET3 ;
    RECT 143.750 0.000 144.160 0.180 ;
  END
  ANTENNADIFFAREA                0.60000         LAYER MET1 ;
  ANTENNADIFFAREA                0.60000         LAYER MET2 ;
  ANTENNADIFFAREA                0.60000         LAYER MET3 ;
  ANTENNAPARTIALMETALAREA        0.94400         LAYER MET1 ;
  ANTENNAPARTIALMETALAREA        1.33320         LAYER MET2 ;
END Q[27]
PIN WEB[27]
  DIRECTION INPUT ;
  PORT
    LAYER MET1 ;
    RECT 142.940 0.000 143.350 0.180 ;
    LAYER MET2 ;
    RECT 142.940 0.000 143.350 0.180 ;
    LAYER MET3 ;
    RECT 142.940 0.000 143.350 0.180 ;
  END
  ANTENNADIFFAREA                0.45930         LAYER MET1 ;
  ANTENNADIFFAREA                0.45930         LAYER MET2 ;
  ANTENNADIFFAREA                0.45930         LAYER MET3 ;
  ANTENNAGATEAREA                0.08100         LAYER MET1 ;
  ANTENNAGATEAREA                0.08100         LAYER MET2 ;
  ANTENNAGATEAREA                0.08100         LAYER MET3 ;
  ANTENNAPARTIALMETALAREA        0.14210         LAYER MET1 ;
  ANTENNAPARTIALMETALAREA        0.09360         LAYER MET2 ;
  ANTENNAMAXAREACAR              1.09630         LAYER MET1 ;
  ANTENNAMAXAREACAR              3.16296         LAYER MET2 ;
  ANTENNAMAXAREACAR              4.07407         LAYER MET3 ;
END WEB[27]
PIN D[28]
  DIRECTION INPUT ;
  PORT
    LAYER MET1 ;
    RECT 149.490 0.000 149.900 0.180 ;
    LAYER MET2 ;
    RECT 149.490 0.000 149.900 0.180 ;
    LAYER MET3 ;
    RECT 149.490 0.000 149.900 0.180 ;
  END
  ANTENNADIFFAREA                0.38930         LAYER MET1 ;
  ANTENNADIFFAREA                0.38930         LAYER MET2 ;
  ANTENNADIFFAREA                0.38930         LAYER MET3 ;
  ANTENNAGATEAREA                0.06300         LAYER MET1 ;
  ANTENNAGATEAREA                0.06300         LAYER MET2 ;
  ANTENNAGATEAREA                0.06300         LAYER MET3 ;
  ANTENNAPARTIALMETALAREA        0.09890         LAYER MET1 ;
  ANTENNAPARTIALMETALAREA        0.10380         LAYER MET2 ;
  ANTENNAMAXAREACAR              0.72381         LAYER MET1 ;
  ANTENNAMAXAREACAR              3.54286         LAYER MET2 ;
  ANTENNAMAXAREACAR              4.71429         LAYER MET3 ;
END D[28]
PIN Q[28]
  DIRECTION OUTPUT ;
  PORT
    LAYER MET1 ;
    RECT 147.950 0.000 148.360 0.180 ;
    LAYER MET2 ;
    RECT 147.950 0.000 148.360 0.180 ;
    LAYER MET3 ;
    RECT 147.950 0.000 148.360 0.180 ;
  END
  ANTENNADIFFAREA                0.60000         LAYER MET1 ;
  ANTENNADIFFAREA                0.60000         LAYER MET2 ;
  ANTENNADIFFAREA                0.60000         LAYER MET3 ;
  ANTENNAPARTIALMETALAREA        0.94400         LAYER MET1 ;
  ANTENNAPARTIALMETALAREA        1.33320         LAYER MET2 ;
END Q[28]
PIN WEB[28]
  DIRECTION INPUT ;
  PORT
    LAYER MET1 ;
    RECT 147.140 0.000 147.550 0.180 ;
    LAYER MET2 ;
    RECT 147.140 0.000 147.550 0.180 ;
    LAYER MET3 ;
    RECT 147.140 0.000 147.550 0.180 ;
  END
  ANTENNADIFFAREA                0.45930         LAYER MET1 ;
  ANTENNADIFFAREA                0.45930         LAYER MET2 ;
  ANTENNADIFFAREA                0.45930         LAYER MET3 ;
  ANTENNAGATEAREA                0.08100         LAYER MET1 ;
  ANTENNAGATEAREA                0.08100         LAYER MET2 ;
  ANTENNAGATEAREA                0.08100         LAYER MET3 ;
  ANTENNAPARTIALMETALAREA        0.14210         LAYER MET1 ;
  ANTENNAPARTIALMETALAREA        0.09360         LAYER MET2 ;
  ANTENNAMAXAREACAR              1.09630         LAYER MET1 ;
  ANTENNAMAXAREACAR              3.16296         LAYER MET2 ;
  ANTENNAMAXAREACAR              4.07407         LAYER MET3 ;
END WEB[28]
PIN D[29]
  DIRECTION INPUT ;
  PORT
    LAYER MET1 ;
    RECT 153.690 0.000 154.100 0.180 ;
    LAYER MET2 ;
    RECT 153.690 0.000 154.100 0.180 ;
    LAYER MET3 ;
    RECT 153.690 0.000 154.100 0.180 ;
  END
  ANTENNADIFFAREA                0.38930         LAYER MET1 ;
  ANTENNADIFFAREA                0.38930         LAYER MET2 ;
  ANTENNADIFFAREA                0.38930         LAYER MET3 ;
  ANTENNAGATEAREA                0.06300         LAYER MET1 ;
  ANTENNAGATEAREA                0.06300         LAYER MET2 ;
  ANTENNAGATEAREA                0.06300         LAYER MET3 ;
  ANTENNAPARTIALMETALAREA        0.09890         LAYER MET1 ;
  ANTENNAPARTIALMETALAREA        0.10380         LAYER MET2 ;
  ANTENNAMAXAREACAR              0.72381         LAYER MET1 ;
  ANTENNAMAXAREACAR              3.54286         LAYER MET2 ;
  ANTENNAMAXAREACAR              4.71429         LAYER MET3 ;
END D[29]
PIN Q[29]
  DIRECTION OUTPUT ;
  PORT
    LAYER MET1 ;
    RECT 152.150 0.000 152.560 0.180 ;
    LAYER MET2 ;
    RECT 152.150 0.000 152.560 0.180 ;
    LAYER MET3 ;
    RECT 152.150 0.000 152.560 0.180 ;
  END
  ANTENNADIFFAREA                0.60000         LAYER MET1 ;
  ANTENNADIFFAREA                0.60000         LAYER MET2 ;
  ANTENNADIFFAREA                0.60000         LAYER MET3 ;
  ANTENNAPARTIALMETALAREA        0.94400         LAYER MET1 ;
  ANTENNAPARTIALMETALAREA        1.33320         LAYER MET2 ;
END Q[29]
PIN WEB[29]
  DIRECTION INPUT ;
  PORT
    LAYER MET1 ;
    RECT 151.340 0.000 151.750 0.180 ;
    LAYER MET2 ;
    RECT 151.340 0.000 151.750 0.180 ;
    LAYER MET3 ;
    RECT 151.340 0.000 151.750 0.180 ;
  END
  ANTENNADIFFAREA                0.45930         LAYER MET1 ;
  ANTENNADIFFAREA                0.45930         LAYER MET2 ;
  ANTENNADIFFAREA                0.45930         LAYER MET3 ;
  ANTENNAGATEAREA                0.08100         LAYER MET1 ;
  ANTENNAGATEAREA                0.08100         LAYER MET2 ;
  ANTENNAGATEAREA                0.08100         LAYER MET3 ;
  ANTENNAPARTIALMETALAREA        0.14210         LAYER MET1 ;
  ANTENNAPARTIALMETALAREA        0.09360         LAYER MET2 ;
  ANTENNAMAXAREACAR              1.09630         LAYER MET1 ;
  ANTENNAMAXAREACAR              3.16296         LAYER MET2 ;
  ANTENNAMAXAREACAR              4.07407         LAYER MET3 ;
END WEB[29]
PIN D[30]
  DIRECTION INPUT ;
  PORT
    LAYER MET1 ;
    RECT 157.890 0.000 158.300 0.180 ;
    LAYER MET2 ;
    RECT 157.890 0.000 158.300 0.180 ;
    LAYER MET3 ;
    RECT 157.890 0.000 158.300 0.180 ;
  END
  ANTENNADIFFAREA                0.38930         LAYER MET1 ;
  ANTENNADIFFAREA                0.38930         LAYER MET2 ;
  ANTENNADIFFAREA                0.38930         LAYER MET3 ;
  ANTENNAGATEAREA                0.06300         LAYER MET1 ;
  ANTENNAGATEAREA                0.06300         LAYER MET2 ;
  ANTENNAGATEAREA                0.06300         LAYER MET3 ;
  ANTENNAPARTIALMETALAREA        0.09890         LAYER MET1 ;
  ANTENNAPARTIALMETALAREA        0.10380         LAYER MET2 ;
  ANTENNAMAXAREACAR              0.72381         LAYER MET1 ;
  ANTENNAMAXAREACAR              3.54286         LAYER MET2 ;
  ANTENNAMAXAREACAR              4.71429         LAYER MET3 ;
END D[30]
PIN Q[30]
  DIRECTION OUTPUT ;
  PORT
    LAYER MET1 ;
    RECT 156.350 0.000 156.760 0.180 ;
    LAYER MET2 ;
    RECT 156.350 0.000 156.760 0.180 ;
    LAYER MET3 ;
    RECT 156.350 0.000 156.760 0.180 ;
  END
  ANTENNADIFFAREA                0.60000         LAYER MET1 ;
  ANTENNADIFFAREA                0.60000         LAYER MET2 ;
  ANTENNADIFFAREA                0.60000         LAYER MET3 ;
  ANTENNAPARTIALMETALAREA        0.94400         LAYER MET1 ;
  ANTENNAPARTIALMETALAREA        1.33320         LAYER MET2 ;
END Q[30]
PIN WEB[30]
  DIRECTION INPUT ;
  PORT
    LAYER MET1 ;
    RECT 155.540 0.000 155.950 0.180 ;
    LAYER MET2 ;
    RECT 155.540 0.000 155.950 0.180 ;
    LAYER MET3 ;
    RECT 155.540 0.000 155.950 0.180 ;
  END
  ANTENNADIFFAREA                0.45930         LAYER MET1 ;
  ANTENNADIFFAREA                0.45930         LAYER MET2 ;
  ANTENNADIFFAREA                0.45930         LAYER MET3 ;
  ANTENNAGATEAREA                0.08100         LAYER MET1 ;
  ANTENNAGATEAREA                0.08100         LAYER MET2 ;
  ANTENNAGATEAREA                0.08100         LAYER MET3 ;
  ANTENNAPARTIALMETALAREA        0.14210         LAYER MET1 ;
  ANTENNAPARTIALMETALAREA        0.09360         LAYER MET2 ;
  ANTENNAMAXAREACAR              1.09630         LAYER MET1 ;
  ANTENNAMAXAREACAR              3.16296         LAYER MET2 ;
  ANTENNAMAXAREACAR              4.07407         LAYER MET3 ;
END WEB[30]
PIN D[31]
  DIRECTION INPUT ;
  PORT
    LAYER MET1 ;
    RECT 162.090 0.000 162.500 0.180 ;
    LAYER MET2 ;
    RECT 162.090 0.000 162.500 0.180 ;
    LAYER MET3 ;
    RECT 162.090 0.000 162.500 0.180 ;
  END
  ANTENNADIFFAREA                0.38930         LAYER MET1 ;
  ANTENNADIFFAREA                0.38930         LAYER MET2 ;
  ANTENNADIFFAREA                0.38930         LAYER MET3 ;
  ANTENNAGATEAREA                0.06300         LAYER MET1 ;
  ANTENNAGATEAREA                0.06300         LAYER MET2 ;
  ANTENNAGATEAREA                0.06300         LAYER MET3 ;
  ANTENNAPARTIALMETALAREA        0.09890         LAYER MET1 ;
  ANTENNAPARTIALMETALAREA        0.10380         LAYER MET2 ;
  ANTENNAMAXAREACAR              0.72381         LAYER MET1 ;
  ANTENNAMAXAREACAR              3.54286         LAYER MET2 ;
  ANTENNAMAXAREACAR              4.71429         LAYER MET3 ;
END D[31]
PIN Q[31]
  DIRECTION OUTPUT ;
  PORT
    LAYER MET1 ;
    RECT 160.550 0.000 160.960 0.180 ;
    LAYER MET2 ;
    RECT 160.550 0.000 160.960 0.180 ;
    LAYER MET3 ;
    RECT 160.550 0.000 160.960 0.180 ;
  END
  ANTENNADIFFAREA                0.60000         LAYER MET1 ;
  ANTENNADIFFAREA                0.60000         LAYER MET2 ;
  ANTENNADIFFAREA                0.60000         LAYER MET3 ;
  ANTENNAPARTIALMETALAREA        0.94400         LAYER MET1 ;
  ANTENNAPARTIALMETALAREA        1.33320         LAYER MET2 ;
END Q[31]
PIN WEB[31]
  DIRECTION INPUT ;
  PORT
    LAYER MET1 ;
    RECT 159.740 0.000 160.150 0.180 ;
    LAYER MET2 ;
    RECT 159.740 0.000 160.150 0.180 ;
    LAYER MET3 ;
    RECT 159.740 0.000 160.150 0.180 ;
  END
  ANTENNADIFFAREA                0.45930         LAYER MET1 ;
  ANTENNADIFFAREA                0.45930         LAYER MET2 ;
  ANTENNADIFFAREA                0.45930         LAYER MET3 ;
  ANTENNAGATEAREA                0.08100         LAYER MET1 ;
  ANTENNAGATEAREA                0.08100         LAYER MET2 ;
  ANTENNAGATEAREA                0.08100         LAYER MET3 ;
  ANTENNAPARTIALMETALAREA        0.14210         LAYER MET1 ;
  ANTENNAPARTIALMETALAREA        0.09360         LAYER MET2 ;
  ANTENNAMAXAREACAR              1.09630         LAYER MET1 ;
  ANTENNAMAXAREACAR              3.16296         LAYER MET2 ;
  ANTENNAMAXAREACAR              4.07407         LAYER MET3 ;
END WEB[31]
OBS
  LAYER MET1 SPACING 0.090 ;
    POLYGON 164.430 0.000 164.430 90.535 
            0.000 90.535 0.000 0.000 
            2.190 0.000 2.190 0.180 
            2.600 0.180 2.600 0.000 
            3.000 0.000 3.000 0.180 
            3.410 0.180 3.410 0.000 
            4.540 0.000 4.540 0.180 
            4.950 0.180 4.950 0.000 
            6.390 0.000 6.390 0.180 
            6.800 0.180 6.800 0.000 
            7.200 0.000 7.200 0.180 
            7.610 0.180 7.610 0.000 
            8.740 0.000 8.740 0.180 
            9.150 0.180 9.150 0.000 
            10.590 0.000 10.590 0.180 
            11.000 0.180 11.000 0.000 
            11.400 0.000 11.400 0.180 
            11.810 0.180 11.810 0.000 
            12.940 0.000 12.940 0.180 
            13.350 0.180 13.350 0.000 
            14.790 0.000 14.790 0.180 
            15.200 0.180 15.200 0.000 
            15.600 0.000 15.600 0.180 
            16.010 0.180 16.010 0.000 
            17.140 0.000 17.140 0.180 
            17.550 0.180 17.550 0.000 
            18.990 0.000 18.990 0.180 
            19.400 0.180 19.400 0.000 
            19.800 0.000 19.800 0.180 
            20.210 0.180 20.210 0.000 
            21.340 0.000 21.340 0.180 
            21.750 0.180 21.750 0.000 
            23.190 0.000 23.190 0.180 
            23.600 0.180 23.600 0.000 
            24.000 0.000 24.000 0.180 
            24.410 0.180 24.410 0.000 
            25.540 0.000 25.540 0.180 
            25.950 0.180 25.950 0.000 
            27.390 0.000 27.390 0.180 
            27.800 0.180 27.800 0.000 
            28.200 0.000 28.200 0.180 
            28.610 0.180 28.610 0.000 
            29.740 0.000 29.740 0.180 
            30.150 0.180 30.150 0.000 
            31.590 0.000 31.590 0.180 
            32.000 0.180 32.000 0.000 
            32.400 0.000 32.400 0.180 
            32.810 0.180 32.810 0.000 
            33.940 0.000 33.940 0.180 
            34.350 0.180 34.350 0.000 
            35.790 0.000 35.790 0.180 
            36.200 0.180 36.200 0.000 
            36.600 0.000 36.600 0.180 
            37.010 0.180 37.010 0.000 
            38.140 0.000 38.140 0.180 
            38.550 0.180 38.550 0.000 
            39.990 0.000 39.990 0.180 
            40.400 0.180 40.400 0.000 
            40.800 0.000 40.800 0.180 
            41.210 0.180 41.210 0.000 
            42.340 0.000 42.340 0.180 
            42.750 0.180 42.750 0.000 
            44.190 0.000 44.190 0.180 
            44.600 0.180 44.600 0.000 
            45.000 0.000 45.000 0.180 
            45.410 0.180 45.410 0.000 
            46.540 0.000 46.540 0.180 
            46.950 0.180 46.950 0.000 
            48.390 0.000 48.390 0.180 
            48.800 0.180 48.800 0.000 
            49.200 0.000 49.200 0.180 
            49.610 0.180 49.610 0.000 
            50.740 0.000 50.740 0.180 
            51.150 0.180 51.150 0.000 
            52.590 0.000 52.590 0.180 
            53.000 0.180 53.000 0.000 
            53.400 0.000 53.400 0.180 
            53.810 0.180 53.810 0.000 
            54.940 0.000 54.940 0.180 
            55.350 0.180 55.350 0.000 
            56.790 0.000 56.790 0.180 
            57.200 0.180 57.200 0.000 
            57.600 0.000 57.600 0.180 
            58.010 0.180 58.010 0.000 
            59.140 0.000 59.140 0.180 
            59.550 0.180 59.550 0.000 
            60.990 0.000 60.990 0.180 
            61.400 0.180 61.400 0.000 
            61.800 0.000 61.800 0.180 
            62.210 0.180 62.210 0.000 
            63.340 0.000 63.340 0.180 
            63.750 0.180 63.750 0.000 
            65.190 0.000 65.190 0.180 
            65.600 0.180 65.600 0.000 
            66.000 0.000 66.000 0.180 
            66.410 0.180 66.410 0.000 
            67.540 0.000 67.540 0.180 
            67.950 0.180 67.950 0.000 
            72.950 0.000 72.950 0.180 
            73.360 0.180 73.360 0.000 
            73.480 0.000 73.480 0.180 
            73.890 0.180 73.890 0.000 
            74.300 0.000 74.300 0.180 
            74.710 0.180 74.710 0.000 
            74.880 0.000 74.880 0.180 
            75.290 0.180 75.290 0.000 
            75.410 0.000 75.410 0.180 
            75.820 0.180 75.820 0.000 
            75.940 0.000 75.940 0.180 
            76.350 0.180 76.350 0.000 
            76.485 0.000 76.485 0.180 
            76.895 0.180 76.895 0.000 
            77.015 0.000 77.015 0.180 
            77.425 0.180 77.425 0.000 
            77.545 0.000 77.545 0.180 
            77.955 0.180 77.955 0.000 
            78.075 0.000 78.075 0.180 
            78.485 0.180 78.485 0.000 
            78.605 0.000 78.605 0.180 
            79.015 0.180 79.015 0.000 
            79.265 0.000 79.265 0.180 
            79.675 0.180 79.675 0.000 
            80.390 0.000 80.390 0.180 
            80.800 0.180 80.800 0.000 
            88.010 0.000 88.010 0.180 
            88.420 0.180 88.420 0.000 
            88.700 0.000 88.700 0.180 
            89.110 0.180 89.110 0.000 
            91.675 0.000 91.675 0.180 
            92.085 0.180 92.085 0.000 
            92.390 0.000 92.390 0.180 
            92.800 0.180 92.800 0.000 
            96.740 0.000 96.740 0.180 
            97.150 0.180 97.150 0.000 
            97.550 0.000 97.550 0.180 
            97.960 0.180 97.960 0.000 
            99.090 0.000 99.090 0.180 
            99.500 0.180 99.500 0.000 
            100.940 0.000 100.940 0.180 
            101.350 0.180 101.350 0.000 
            101.750 0.000 101.750 0.180 
            102.160 0.180 102.160 0.000 
            103.290 0.000 103.290 0.180 
            103.700 0.180 103.700 0.000 
            105.140 0.000 105.140 0.180 
            105.550 0.180 105.550 0.000 
            105.950 0.000 105.950 0.180 
            106.360 0.180 106.360 0.000 
            107.490 0.000 107.490 0.180 
            107.900 0.180 107.900 0.000 
            109.340 0.000 109.340 0.180 
            109.750 0.180 109.750 0.000 
            110.150 0.000 110.150 0.180 
            110.560 0.180 110.560 0.000 
            111.690 0.000 111.690 0.180 
            112.100 0.180 112.100 0.000 
            113.540 0.000 113.540 0.180 
            113.950 0.180 113.950 0.000 
            114.350 0.000 114.350 0.180 
            114.760 0.180 114.760 0.000 
            115.890 0.000 115.890 0.180 
            116.300 0.180 116.300 0.000 
            117.740 0.000 117.740 0.180 
            118.150 0.180 118.150 0.000 
            118.550 0.000 118.550 0.180 
            118.960 0.180 118.960 0.000 
            120.090 0.000 120.090 0.180 
            120.500 0.180 120.500 0.000 
            121.940 0.000 121.940 0.180 
            122.350 0.180 122.350 0.000 
            122.750 0.000 122.750 0.180 
            123.160 0.180 123.160 0.000 
            124.290 0.000 124.290 0.180 
            124.700 0.180 124.700 0.000 
            126.140 0.000 126.140 0.180 
            126.550 0.180 126.550 0.000 
            126.950 0.000 126.950 0.180 
            127.360 0.180 127.360 0.000 
            128.490 0.000 128.490 0.180 
            128.900 0.180 128.900 0.000 
            130.340 0.000 130.340 0.180 
            130.750 0.180 130.750 0.000 
            131.150 0.000 131.150 0.180 
            131.560 0.180 131.560 0.000 
            132.690 0.000 132.690 0.180 
            133.100 0.180 133.100 0.000 
            134.540 0.000 134.540 0.180 
            134.950 0.180 134.950 0.000 
            135.350 0.000 135.350 0.180 
            135.760 0.180 135.760 0.000 
            136.890 0.000 136.890 0.180 
            137.300 0.180 137.300 0.000 
            138.740 0.000 138.740 0.180 
            139.150 0.180 139.150 0.000 
            139.550 0.000 139.550 0.180 
            139.960 0.180 139.960 0.000 
            141.090 0.000 141.090 0.180 
            141.500 0.180 141.500 0.000 
            142.940 0.000 142.940 0.180 
            143.350 0.180 143.350 0.000 
            143.750 0.000 143.750 0.180 
            144.160 0.180 144.160 0.000 
            145.290 0.000 145.290 0.180 
            145.700 0.180 145.700 0.000 
            147.140 0.000 147.140 0.180 
            147.550 0.180 147.550 0.000 
            147.950 0.000 147.950 0.180 
            148.360 0.180 148.360 0.000 
            149.490 0.000 149.490 0.180 
            149.900 0.180 149.900 0.000 
            151.340 0.000 151.340 0.180 
            151.750 0.180 151.750 0.000 
            152.150 0.000 152.150 0.180 
            152.560 0.180 152.560 0.000 
            153.690 0.000 153.690 0.180 
            154.100 0.180 154.100 0.000 
            155.540 0.000 155.540 0.180 
            155.950 0.180 155.950 0.000 
            156.350 0.000 156.350 0.180 
            156.760 0.180 156.760 0.000 
            157.890 0.000 157.890 0.180 
            158.300 0.180 158.300 0.000 
            159.740 0.000 159.740 0.180 
            160.150 0.180 160.150 0.000 
            160.550 0.000 160.550 0.180 
            160.960 0.180 160.960 0.000 
            162.090 0.000 162.090 0.180 
            162.500 0.180 162.500 0.000 
            164.430 0.000 ;
  LAYER VIA1 SPACING 0.110 ;
    RECT 0.000 0.000 164.430 90.535 ;
  LAYER MET2 SPACING 0.100 ;
    POLYGON 164.430 0.000 164.430 90.535 
            0.000 90.535 0.000 0.000 
            2.190 0.000 2.190 0.180 
            2.600 0.180 2.600 0.000 
            3.000 0.000 3.000 0.180 
            3.410 0.180 3.410 0.000 
            4.540 0.000 4.540 0.180 
            4.950 0.180 4.950 0.000 
            6.390 0.000 6.390 0.180 
            6.800 0.180 6.800 0.000 
            7.200 0.000 7.200 0.180 
            7.610 0.180 7.610 0.000 
            8.740 0.000 8.740 0.180 
            9.150 0.180 9.150 0.000 
            10.590 0.000 10.590 0.180 
            11.000 0.180 11.000 0.000 
            11.400 0.000 11.400 0.180 
            11.810 0.180 11.810 0.000 
            12.940 0.000 12.940 0.180 
            13.350 0.180 13.350 0.000 
            14.790 0.000 14.790 0.180 
            15.200 0.180 15.200 0.000 
            15.600 0.000 15.600 0.180 
            16.010 0.180 16.010 0.000 
            17.140 0.000 17.140 0.180 
            17.550 0.180 17.550 0.000 
            18.990 0.000 18.990 0.180 
            19.400 0.180 19.400 0.000 
            19.800 0.000 19.800 0.180 
            20.210 0.180 20.210 0.000 
            21.340 0.000 21.340 0.180 
            21.750 0.180 21.750 0.000 
            23.190 0.000 23.190 0.180 
            23.600 0.180 23.600 0.000 
            24.000 0.000 24.000 0.180 
            24.410 0.180 24.410 0.000 
            25.540 0.000 25.540 0.180 
            25.950 0.180 25.950 0.000 
            27.390 0.000 27.390 0.180 
            27.800 0.180 27.800 0.000 
            28.200 0.000 28.200 0.180 
            28.610 0.180 28.610 0.000 
            29.740 0.000 29.740 0.180 
            30.150 0.180 30.150 0.000 
            31.590 0.000 31.590 0.180 
            32.000 0.180 32.000 0.000 
            32.400 0.000 32.400 0.180 
            32.810 0.180 32.810 0.000 
            33.940 0.000 33.940 0.180 
            34.350 0.180 34.350 0.000 
            35.790 0.000 35.790 0.180 
            36.200 0.180 36.200 0.000 
            36.600 0.000 36.600 0.180 
            37.010 0.180 37.010 0.000 
            38.140 0.000 38.140 0.180 
            38.550 0.180 38.550 0.000 
            39.990 0.000 39.990 0.180 
            40.400 0.180 40.400 0.000 
            40.800 0.000 40.800 0.180 
            41.210 0.180 41.210 0.000 
            42.340 0.000 42.340 0.180 
            42.750 0.180 42.750 0.000 
            44.190 0.000 44.190 0.180 
            44.600 0.180 44.600 0.000 
            45.000 0.000 45.000 0.180 
            45.410 0.180 45.410 0.000 
            46.540 0.000 46.540 0.180 
            46.950 0.180 46.950 0.000 
            48.390 0.000 48.390 0.180 
            48.800 0.180 48.800 0.000 
            49.200 0.000 49.200 0.180 
            49.610 0.180 49.610 0.000 
            50.740 0.000 50.740 0.180 
            51.150 0.180 51.150 0.000 
            52.590 0.000 52.590 0.180 
            53.000 0.180 53.000 0.000 
            53.400 0.000 53.400 0.180 
            53.810 0.180 53.810 0.000 
            54.940 0.000 54.940 0.180 
            55.350 0.180 55.350 0.000 
            56.790 0.000 56.790 0.180 
            57.200 0.180 57.200 0.000 
            57.600 0.000 57.600 0.180 
            58.010 0.180 58.010 0.000 
            59.140 0.000 59.140 0.180 
            59.550 0.180 59.550 0.000 
            60.990 0.000 60.990 0.180 
            61.400 0.180 61.400 0.000 
            61.800 0.000 61.800 0.180 
            62.210 0.180 62.210 0.000 
            63.340 0.000 63.340 0.180 
            63.750 0.180 63.750 0.000 
            65.190 0.000 65.190 0.180 
            65.600 0.180 65.600 0.000 
            66.000 0.000 66.000 0.180 
            66.410 0.180 66.410 0.000 
            67.540 0.000 67.540 0.180 
            67.950 0.180 67.950 0.000 
            72.950 0.000 72.950 0.180 
            73.360 0.180 73.360 0.000 
            73.480 0.000 73.480 0.180 
            73.890 0.180 73.890 0.000 
            74.300 0.000 74.300 0.180 
            74.710 0.180 74.710 0.000 
            74.880 0.000 74.880 0.180 
            75.290 0.180 75.290 0.000 
            75.410 0.000 75.410 0.180 
            75.820 0.180 75.820 0.000 
            75.940 0.000 75.940 0.180 
            76.350 0.180 76.350 0.000 
            76.485 0.000 76.485 0.180 
            76.895 0.180 76.895 0.000 
            77.015 0.000 77.015 0.180 
            77.425 0.180 77.425 0.000 
            77.545 0.000 77.545 0.180 
            77.955 0.180 77.955 0.000 
            78.075 0.000 78.075 0.180 
            78.485 0.180 78.485 0.000 
            78.605 0.000 78.605 0.180 
            79.015 0.180 79.015 0.000 
            79.265 0.000 79.265 0.180 
            79.675 0.180 79.675 0.000 
            80.390 0.000 80.390 0.180 
            80.800 0.180 80.800 0.000 
            88.010 0.000 88.010 0.180 
            88.420 0.180 88.420 0.000 
            88.700 0.000 88.700 0.180 
            89.110 0.180 89.110 0.000 
            91.675 0.000 91.675 0.180 
            92.085 0.180 92.085 0.000 
            92.390 0.000 92.390 0.180 
            92.800 0.180 92.800 0.000 
            96.740 0.000 96.740 0.180 
            97.150 0.180 97.150 0.000 
            97.550 0.000 97.550 0.180 
            97.960 0.180 97.960 0.000 
            99.090 0.000 99.090 0.180 
            99.500 0.180 99.500 0.000 
            100.940 0.000 100.940 0.180 
            101.350 0.180 101.350 0.000 
            101.750 0.000 101.750 0.180 
            102.160 0.180 102.160 0.000 
            103.290 0.000 103.290 0.180 
            103.700 0.180 103.700 0.000 
            105.140 0.000 105.140 0.180 
            105.550 0.180 105.550 0.000 
            105.950 0.000 105.950 0.180 
            106.360 0.180 106.360 0.000 
            107.490 0.000 107.490 0.180 
            107.900 0.180 107.900 0.000 
            109.340 0.000 109.340 0.180 
            109.750 0.180 109.750 0.000 
            110.150 0.000 110.150 0.180 
            110.560 0.180 110.560 0.000 
            111.690 0.000 111.690 0.180 
            112.100 0.180 112.100 0.000 
            113.540 0.000 113.540 0.180 
            113.950 0.180 113.950 0.000 
            114.350 0.000 114.350 0.180 
            114.760 0.180 114.760 0.000 
            115.890 0.000 115.890 0.180 
            116.300 0.180 116.300 0.000 
            117.740 0.000 117.740 0.180 
            118.150 0.180 118.150 0.000 
            118.550 0.000 118.550 0.180 
            118.960 0.180 118.960 0.000 
            120.090 0.000 120.090 0.180 
            120.500 0.180 120.500 0.000 
            121.940 0.000 121.940 0.180 
            122.350 0.180 122.350 0.000 
            122.750 0.000 122.750 0.180 
            123.160 0.180 123.160 0.000 
            124.290 0.000 124.290 0.180 
            124.700 0.180 124.700 0.000 
            126.140 0.000 126.140 0.180 
            126.550 0.180 126.550 0.000 
            126.950 0.000 126.950 0.180 
            127.360 0.180 127.360 0.000 
            128.490 0.000 128.490 0.180 
            128.900 0.180 128.900 0.000 
            130.340 0.000 130.340 0.180 
            130.750 0.180 130.750 0.000 
            131.150 0.000 131.150 0.180 
            131.560 0.180 131.560 0.000 
            132.690 0.000 132.690 0.180 
            133.100 0.180 133.100 0.000 
            134.540 0.000 134.540 0.180 
            134.950 0.180 134.950 0.000 
            135.350 0.000 135.350 0.180 
            135.760 0.180 135.760 0.000 
            136.890 0.000 136.890 0.180 
            137.300 0.180 137.300 0.000 
            138.740 0.000 138.740 0.180 
            139.150 0.180 139.150 0.000 
            139.550 0.000 139.550 0.180 
            139.960 0.180 139.960 0.000 
            141.090 0.000 141.090 0.180 
            141.500 0.180 141.500 0.000 
            142.940 0.000 142.940 0.180 
            143.350 0.180 143.350 0.000 
            143.750 0.000 143.750 0.180 
            144.160 0.180 144.160 0.000 
            145.290 0.000 145.290 0.180 
            145.700 0.180 145.700 0.000 
            147.140 0.000 147.140 0.180 
            147.550 0.180 147.550 0.000 
            147.950 0.000 147.950 0.180 
            148.360 0.180 148.360 0.000 
            149.490 0.000 149.490 0.180 
            149.900 0.180 149.900 0.000 
            151.340 0.000 151.340 0.180 
            151.750 0.180 151.750 0.000 
            152.150 0.000 152.150 0.180 
            152.560 0.180 152.560 0.000 
            153.690 0.000 153.690 0.180 
            154.100 0.180 154.100 0.000 
            155.540 0.000 155.540 0.180 
            155.950 0.180 155.950 0.000 
            156.350 0.000 156.350 0.180 
            156.760 0.180 156.760 0.000 
            157.890 0.000 157.890 0.180 
            158.300 0.180 158.300 0.000 
            159.740 0.000 159.740 0.180 
            160.150 0.180 160.150 0.000 
            160.550 0.000 160.550 0.180 
            160.960 0.180 160.960 0.000 
            162.090 0.000 162.090 0.180 
            162.500 0.180 162.500 0.000 
            164.430 0.000 ;
  LAYER VIA2 SPACING 0.110 ;
    RECT 0.000 0.000 164.430 90.535 ;
  LAYER MET3 SPACING 0.150 ;
    POLYGON 164.430 0.000 164.430 90.535 
            0.000 90.535 0.000 0.000 
            2.190 0.000 2.190 0.180 
            2.600 0.180 2.600 0.000 
            3.000 0.000 3.000 0.180 
            3.410 0.180 3.410 0.000 
            4.540 0.000 4.540 0.180 
            4.950 0.180 4.950 0.000 
            6.390 0.000 6.390 0.180 
            6.800 0.180 6.800 0.000 
            7.200 0.000 7.200 0.180 
            7.610 0.180 7.610 0.000 
            8.740 0.000 8.740 0.180 
            9.150 0.180 9.150 0.000 
            10.590 0.000 10.590 0.180 
            11.000 0.180 11.000 0.000 
            11.400 0.000 11.400 0.180 
            11.810 0.180 11.810 0.000 
            12.940 0.000 12.940 0.180 
            13.350 0.180 13.350 0.000 
            14.790 0.000 14.790 0.180 
            15.200 0.180 15.200 0.000 
            15.600 0.000 15.600 0.180 
            16.010 0.180 16.010 0.000 
            17.140 0.000 17.140 0.180 
            17.550 0.180 17.550 0.000 
            18.990 0.000 18.990 0.180 
            19.400 0.180 19.400 0.000 
            19.800 0.000 19.800 0.180 
            20.210 0.180 20.210 0.000 
            21.340 0.000 21.340 0.180 
            21.750 0.180 21.750 0.000 
            23.190 0.000 23.190 0.180 
            23.600 0.180 23.600 0.000 
            24.000 0.000 24.000 0.180 
            24.410 0.180 24.410 0.000 
            25.540 0.000 25.540 0.180 
            25.950 0.180 25.950 0.000 
            27.390 0.000 27.390 0.180 
            27.800 0.180 27.800 0.000 
            28.200 0.000 28.200 0.180 
            28.610 0.180 28.610 0.000 
            29.740 0.000 29.740 0.180 
            30.150 0.180 30.150 0.000 
            31.590 0.000 31.590 0.180 
            32.000 0.180 32.000 0.000 
            32.400 0.000 32.400 0.180 
            32.810 0.180 32.810 0.000 
            33.940 0.000 33.940 0.180 
            34.350 0.180 34.350 0.000 
            35.790 0.000 35.790 0.180 
            36.200 0.180 36.200 0.000 
            36.600 0.000 36.600 0.180 
            37.010 0.180 37.010 0.000 
            38.140 0.000 38.140 0.180 
            38.550 0.180 38.550 0.000 
            39.990 0.000 39.990 0.180 
            40.400 0.180 40.400 0.000 
            40.800 0.000 40.800 0.180 
            41.210 0.180 41.210 0.000 
            42.340 0.000 42.340 0.180 
            42.750 0.180 42.750 0.000 
            44.190 0.000 44.190 0.180 
            44.600 0.180 44.600 0.000 
            45.000 0.000 45.000 0.180 
            45.410 0.180 45.410 0.000 
            46.540 0.000 46.540 0.180 
            46.950 0.180 46.950 0.000 
            48.390 0.000 48.390 0.180 
            48.800 0.180 48.800 0.000 
            49.200 0.000 49.200 0.180 
            49.610 0.180 49.610 0.000 
            50.740 0.000 50.740 0.180 
            51.150 0.180 51.150 0.000 
            52.590 0.000 52.590 0.180 
            53.000 0.180 53.000 0.000 
            53.400 0.000 53.400 0.180 
            53.810 0.180 53.810 0.000 
            54.940 0.000 54.940 0.180 
            55.350 0.180 55.350 0.000 
            56.790 0.000 56.790 0.180 
            57.200 0.180 57.200 0.000 
            57.600 0.000 57.600 0.180 
            58.010 0.180 58.010 0.000 
            59.140 0.000 59.140 0.180 
            59.550 0.180 59.550 0.000 
            60.990 0.000 60.990 0.180 
            61.400 0.180 61.400 0.000 
            61.800 0.000 61.800 0.180 
            62.210 0.180 62.210 0.000 
            63.340 0.000 63.340 0.180 
            63.750 0.180 63.750 0.000 
            65.190 0.000 65.190 0.180 
            65.600 0.180 65.600 0.000 
            66.000 0.000 66.000 0.180 
            66.410 0.180 66.410 0.000 
            67.540 0.000 67.540 0.180 
            67.950 0.180 67.950 0.000 
            72.950 0.000 72.950 0.180 
            73.360 0.180 73.360 0.000 
            73.480 0.000 73.480 0.180 
            73.890 0.180 73.890 0.000 
            74.300 0.000 74.300 0.180 
            74.710 0.180 74.710 0.000 
            74.880 0.000 74.880 0.180 
            75.290 0.180 75.290 0.000 
            75.410 0.000 75.410 0.180 
            75.820 0.180 75.820 0.000 
            75.940 0.000 75.940 0.180 
            76.350 0.180 76.350 0.000 
            76.485 0.000 76.485 0.180 
            76.895 0.180 76.895 0.000 
            77.015 0.000 77.015 0.180 
            77.425 0.180 77.425 0.000 
            77.545 0.000 77.545 0.180 
            77.955 0.180 77.955 0.000 
            78.075 0.000 78.075 0.180 
            78.485 0.180 78.485 0.000 
            78.605 0.000 78.605 0.180 
            79.015 0.180 79.015 0.000 
            79.265 0.000 79.265 0.180 
            79.675 0.180 79.675 0.000 
            80.390 0.000 80.390 0.180 
            80.800 0.180 80.800 0.000 
            88.010 0.000 88.010 0.180 
            88.420 0.180 88.420 0.000 
            88.700 0.000 88.700 0.180 
            89.110 0.180 89.110 0.000 
            91.675 0.000 91.675 0.180 
            92.085 0.180 92.085 0.000 
            92.390 0.000 92.390 0.180 
            92.800 0.180 92.800 0.000 
            96.740 0.000 96.740 0.180 
            97.150 0.180 97.150 0.000 
            97.550 0.000 97.550 0.180 
            97.960 0.180 97.960 0.000 
            99.090 0.000 99.090 0.180 
            99.500 0.180 99.500 0.000 
            100.940 0.000 100.940 0.180 
            101.350 0.180 101.350 0.000 
            101.750 0.000 101.750 0.180 
            102.160 0.180 102.160 0.000 
            103.290 0.000 103.290 0.180 
            103.700 0.180 103.700 0.000 
            105.140 0.000 105.140 0.180 
            105.550 0.180 105.550 0.000 
            105.950 0.000 105.950 0.180 
            106.360 0.180 106.360 0.000 
            107.490 0.000 107.490 0.180 
            107.900 0.180 107.900 0.000 
            109.340 0.000 109.340 0.180 
            109.750 0.180 109.750 0.000 
            110.150 0.000 110.150 0.180 
            110.560 0.180 110.560 0.000 
            111.690 0.000 111.690 0.180 
            112.100 0.180 112.100 0.000 
            113.540 0.000 113.540 0.180 
            113.950 0.180 113.950 0.000 
            114.350 0.000 114.350 0.180 
            114.760 0.180 114.760 0.000 
            115.890 0.000 115.890 0.180 
            116.300 0.180 116.300 0.000 
            117.740 0.000 117.740 0.180 
            118.150 0.180 118.150 0.000 
            118.550 0.000 118.550 0.180 
            118.960 0.180 118.960 0.000 
            120.090 0.000 120.090 0.180 
            120.500 0.180 120.500 0.000 
            121.940 0.000 121.940 0.180 
            122.350 0.180 122.350 0.000 
            122.750 0.000 122.750 0.180 
            123.160 0.180 123.160 0.000 
            124.290 0.000 124.290 0.180 
            124.700 0.180 124.700 0.000 
            126.140 0.000 126.140 0.180 
            126.550 0.180 126.550 0.000 
            126.950 0.000 126.950 0.180 
            127.360 0.180 127.360 0.000 
            128.490 0.000 128.490 0.180 
            128.900 0.180 128.900 0.000 
            130.340 0.000 130.340 0.180 
            130.750 0.180 130.750 0.000 
            131.150 0.000 131.150 0.180 
            131.560 0.180 131.560 0.000 
            132.690 0.000 132.690 0.180 
            133.100 0.180 133.100 0.000 
            134.540 0.000 134.540 0.180 
            134.950 0.180 134.950 0.000 
            135.350 0.000 135.350 0.180 
            135.760 0.180 135.760 0.000 
            136.890 0.000 136.890 0.180 
            137.300 0.180 137.300 0.000 
            138.740 0.000 138.740 0.180 
            139.150 0.180 139.150 0.000 
            139.550 0.000 139.550 0.180 
            139.960 0.180 139.960 0.000 
            141.090 0.000 141.090 0.180 
            141.500 0.180 141.500 0.000 
            142.940 0.000 142.940 0.180 
            143.350 0.180 143.350 0.000 
            143.750 0.000 143.750 0.180 
            144.160 0.180 144.160 0.000 
            145.290 0.000 145.290 0.180 
            145.700 0.180 145.700 0.000 
            147.140 0.000 147.140 0.180 
            147.550 0.180 147.550 0.000 
            147.950 0.000 147.950 0.180 
            148.360 0.180 148.360 0.000 
            149.490 0.000 149.490 0.180 
            149.900 0.180 149.900 0.000 
            151.340 0.000 151.340 0.180 
            151.750 0.180 151.750 0.000 
            152.150 0.000 152.150 0.180 
            152.560 0.180 152.560 0.000 
            153.690 0.000 153.690 0.180 
            154.100 0.180 154.100 0.000 
            155.540 0.000 155.540 0.180 
            155.950 0.180 155.950 0.000 
            156.350 0.000 156.350 0.180 
            156.760 0.180 156.760 0.000 
            157.890 0.000 157.890 0.180 
            158.300 0.180 158.300 0.000 
            159.740 0.000 159.740 0.180 
            160.150 0.180 160.150 0.000 
            160.550 0.000 160.550 0.180 
            160.960 0.180 160.960 0.000 
            162.090 0.000 162.090 0.180 
            162.500 0.180 162.500 0.000 
            164.430 0.000 ;
  LAYER VIA3 SPACING 0.110 ;
    RECT 0.000 0.000 164.430 90.535 ;
  LAYER MET4 SPACING 0.150 ;
    RECT 0.000 0.000 0.075 90.535 ;
    RECT 0.485 0.000 0.605 90.535 ;
    RECT 1.015 0.000 1.135 90.535 ;
    RECT 1.545 0.000 1.735 90.535 ;
    RECT 2.145 0.000 2.335 90.535 ;
    RECT 2.745 0.000 2.935 90.535 ;
    RECT 3.345 0.000 3.535 90.535 ;
    RECT 3.945 0.000 4.135 90.535 ;
    RECT 4.545 0.000 4.735 90.535 ;
    RECT 5.145 0.000 5.335 90.535 ;
    RECT 5.745 0.000 5.935 90.535 ;
    RECT 6.345 0.000 6.535 90.535 ;
    RECT 6.945 0.000 7.135 90.535 ;
    RECT 7.545 0.000 7.735 90.535 ;
    RECT 8.145 0.000 8.335 90.535 ;
    RECT 8.745 0.000 8.935 90.535 ;
    RECT 9.345 0.000 9.535 90.535 ;
    RECT 9.945 0.000 10.135 90.535 ;
    RECT 10.545 0.000 10.735 90.535 ;
    RECT 11.145 0.000 11.335 90.535 ;
    RECT 11.745 0.000 11.935 90.535 ;
    RECT 12.345 0.000 12.535 90.535 ;
    RECT 12.945 0.000 13.135 90.535 ;
    RECT 13.545 0.000 13.735 90.535 ;
    RECT 14.145 0.000 14.335 90.535 ;
    RECT 14.745 0.000 14.935 90.535 ;
    RECT 15.345 0.000 15.535 90.535 ;
    RECT 15.945 0.000 16.135 90.535 ;
    RECT 16.545 0.000 16.735 90.535 ;
    RECT 17.145 0.000 17.335 90.535 ;
    RECT 17.745 0.000 17.935 90.535 ;
    RECT 18.345 0.000 18.535 90.535 ;
    RECT 18.945 0.000 19.135 90.535 ;
    RECT 19.545 0.000 19.735 90.535 ;
    RECT 20.145 0.000 20.335 90.535 ;
    RECT 20.745 0.000 20.935 90.535 ;
    RECT 21.345 0.000 21.535 90.535 ;
    RECT 21.945 0.000 22.135 90.535 ;
    RECT 22.545 0.000 22.735 90.535 ;
    RECT 23.145 0.000 23.335 90.535 ;
    RECT 23.745 0.000 23.935 90.535 ;
    RECT 24.345 0.000 24.535 90.535 ;
    RECT 24.945 0.000 25.135 90.535 ;
    RECT 25.545 0.000 25.735 90.535 ;
    RECT 26.145 0.000 26.335 90.535 ;
    RECT 26.745 0.000 26.935 90.535 ;
    RECT 27.345 0.000 27.535 90.535 ;
    RECT 27.945 0.000 28.135 90.535 ;
    RECT 28.545 0.000 28.735 90.535 ;
    RECT 29.145 0.000 29.335 90.535 ;
    RECT 29.745 0.000 29.935 90.535 ;
    RECT 30.345 0.000 30.535 90.535 ;
    RECT 30.945 0.000 31.135 90.535 ;
    RECT 31.545 0.000 31.735 90.535 ;
    RECT 32.145 0.000 32.335 90.535 ;
    RECT 32.745 0.000 32.935 90.535 ;
    RECT 33.345 0.000 33.535 90.535 ;
    RECT 33.945 0.000 34.135 90.535 ;
    RECT 34.545 0.000 34.735 90.535 ;
    RECT 35.145 0.000 35.335 90.535 ;
    RECT 35.745 0.000 35.935 90.535 ;
    RECT 36.345 0.000 36.535 90.535 ;
    RECT 36.945 0.000 37.135 90.535 ;
    RECT 37.545 0.000 37.735 90.535 ;
    RECT 38.145 0.000 38.335 90.535 ;
    RECT 38.745 0.000 38.935 90.535 ;
    RECT 39.345 0.000 39.535 90.535 ;
    RECT 39.945 0.000 40.135 90.535 ;
    RECT 40.545 0.000 40.735 90.535 ;
    RECT 41.145 0.000 41.335 90.535 ;
    RECT 41.745 0.000 41.935 90.535 ;
    RECT 42.345 0.000 42.535 90.535 ;
    RECT 42.945 0.000 43.135 90.535 ;
    RECT 43.545 0.000 43.735 90.535 ;
    RECT 44.145 0.000 44.335 90.535 ;
    RECT 44.745 0.000 44.935 90.535 ;
    RECT 45.345 0.000 45.535 90.535 ;
    RECT 45.945 0.000 46.135 90.535 ;
    RECT 46.545 0.000 46.735 90.535 ;
    RECT 47.145 0.000 47.335 90.535 ;
    RECT 47.745 0.000 47.935 90.535 ;
    RECT 48.345 0.000 48.535 90.535 ;
    RECT 48.945 0.000 49.135 90.535 ;
    RECT 49.545 0.000 49.735 90.535 ;
    RECT 50.145 0.000 50.335 90.535 ;
    RECT 50.745 0.000 50.935 90.535 ;
    RECT 51.345 0.000 51.535 90.535 ;
    RECT 51.945 0.000 52.135 90.535 ;
    RECT 52.545 0.000 52.735 90.535 ;
    RECT 53.145 0.000 53.335 90.535 ;
    RECT 53.745 0.000 53.935 90.535 ;
    RECT 54.345 0.000 54.535 90.535 ;
    RECT 54.945 0.000 55.135 90.535 ;
    RECT 55.545 0.000 55.735 90.535 ;
    RECT 56.145 0.000 56.335 90.535 ;
    RECT 56.745 0.000 56.935 90.535 ;
    RECT 57.345 0.000 57.535 90.535 ;
    RECT 57.945 0.000 58.135 90.535 ;
    RECT 58.545 0.000 58.735 90.535 ;
    RECT 59.145 0.000 59.335 90.535 ;
    RECT 59.745 0.000 59.935 90.535 ;
    RECT 60.345 0.000 60.535 90.535 ;
    RECT 60.945 0.000 61.135 90.535 ;
    RECT 61.545 0.000 61.735 90.535 ;
    RECT 62.145 0.000 62.335 90.535 ;
    RECT 62.745 0.000 62.935 90.535 ;
    RECT 63.345 0.000 63.535 90.535 ;
    RECT 63.945 0.000 64.135 90.535 ;
    RECT 64.545 0.000 64.735 90.535 ;
    RECT 65.145 0.000 65.335 90.535 ;
    RECT 65.745 0.000 65.935 90.535 ;
    RECT 66.345 0.000 66.535 90.535 ;
    RECT 66.945 0.000 67.135 90.535 ;
    RECT 67.545 0.000 67.735 90.535 ;
    RECT 68.145 0.000 68.335 90.535 ;
    RECT 68.745 0.000 68.865 90.535 ;
    RECT 69.275 0.000 69.395 90.535 ;
    RECT 69.805 0.000 70.230 90.535 ;
    RECT 70.640 0.000 70.760 90.535 ;
    RECT 71.170 0.000 71.290 90.535 ;
    RECT 71.700 0.000 71.820 90.535 ;
    RECT 72.230 0.000 72.350 90.535 ;
    RECT 72.760 0.000 72.880 90.535 ;
    RECT 73.290 0.000 73.410 90.535 ;
    RECT 73.820 0.000 73.940 90.535 ;
    RECT 74.350 0.000 74.470 90.535 ;
    RECT 74.880 0.000 75.000 90.535 ;
    RECT 75.410 0.000 75.530 90.535 ;
    RECT 75.940 0.000 76.060 90.535 ;
    RECT 76.470 0.000 76.590 90.535 ;
    RECT 77.000 0.000 77.120 90.535 ;
    RECT 77.530 0.000 77.650 90.535 ;
    RECT 78.060 0.000 78.180 90.535 ;
    RECT 78.590 0.000 78.710 90.535 ;
    RECT 79.120 0.000 79.240 90.535 ;
    RECT 79.650 0.000 79.770 90.535 ;
    RECT 80.180 0.000 80.300 90.535 ;
    RECT 80.710 0.000 80.830 90.535 ;
    RECT 81.240 0.000 81.360 90.535 ;
    RECT 81.770 0.000 81.890 90.535 ;
    RECT 82.300 0.000 82.420 90.535 ;
    RECT 82.830 0.000 82.950 90.535 ;
    RECT 83.360 0.000 83.480 90.535 ;
    RECT 83.890 0.000 84.010 90.535 ;
    RECT 84.420 0.000 84.540 90.535 ;
    RECT 84.950 0.000 85.070 90.535 ;
    RECT 85.480 0.000 85.600 90.535 ;
    RECT 86.010 0.000 86.130 90.535 ;
    RECT 86.540 0.000 86.660 90.535 ;
    RECT 87.070 0.000 87.190 90.535 ;
    RECT 87.600 0.000 87.720 90.535 ;
    RECT 88.130 0.000 88.250 90.535 ;
    RECT 88.660 0.000 88.780 90.535 ;
    RECT 89.190 0.000 89.310 90.535 ;
    RECT 89.720 0.000 89.840 90.535 ;
    RECT 90.250 0.000 90.370 90.535 ;
    RECT 90.780 0.000 90.900 90.535 ;
    RECT 91.310 0.000 91.430 90.535 ;
    RECT 91.840 0.000 91.960 90.535 ;
    RECT 92.370 0.000 92.490 90.535 ;
    RECT 92.900 0.000 93.020 90.535 ;
    RECT 93.430 0.000 93.550 90.535 ;
    RECT 93.960 0.000 94.080 90.535 ;
    RECT 94.490 0.000 94.625 90.535 ;
    RECT 95.035 0.000 95.155 90.535 ;
    RECT 95.565 0.000 95.685 90.535 ;
    RECT 96.095 0.000 96.285 90.535 ;
    RECT 96.695 0.000 96.885 90.535 ;
    RECT 97.295 0.000 97.485 90.535 ;
    RECT 97.895 0.000 98.085 90.535 ;
    RECT 98.495 0.000 98.685 90.535 ;
    RECT 99.095 0.000 99.285 90.535 ;
    RECT 99.695 0.000 99.885 90.535 ;
    RECT 100.295 0.000 100.485 90.535 ;
    RECT 100.895 0.000 101.085 90.535 ;
    RECT 101.495 0.000 101.685 90.535 ;
    RECT 102.095 0.000 102.285 90.535 ;
    RECT 102.695 0.000 102.885 90.535 ;
    RECT 103.295 0.000 103.485 90.535 ;
    RECT 103.895 0.000 104.085 90.535 ;
    RECT 104.495 0.000 104.685 90.535 ;
    RECT 105.095 0.000 105.285 90.535 ;
    RECT 105.695 0.000 105.885 90.535 ;
    RECT 106.295 0.000 106.485 90.535 ;
    RECT 106.895 0.000 107.085 90.535 ;
    RECT 107.495 0.000 107.685 90.535 ;
    RECT 108.095 0.000 108.285 90.535 ;
    RECT 108.695 0.000 108.885 90.535 ;
    RECT 109.295 0.000 109.485 90.535 ;
    RECT 109.895 0.000 110.085 90.535 ;
    RECT 110.495 0.000 110.685 90.535 ;
    RECT 111.095 0.000 111.285 90.535 ;
    RECT 111.695 0.000 111.885 90.535 ;
    RECT 112.295 0.000 112.485 90.535 ;
    RECT 112.895 0.000 113.085 90.535 ;
    RECT 113.495 0.000 113.685 90.535 ;
    RECT 114.095 0.000 114.285 90.535 ;
    RECT 114.695 0.000 114.885 90.535 ;
    RECT 115.295 0.000 115.485 90.535 ;
    RECT 115.895 0.000 116.085 90.535 ;
    RECT 116.495 0.000 116.685 90.535 ;
    RECT 117.095 0.000 117.285 90.535 ;
    RECT 117.695 0.000 117.885 90.535 ;
    RECT 118.295 0.000 118.485 90.535 ;
    RECT 118.895 0.000 119.085 90.535 ;
    RECT 119.495 0.000 119.685 90.535 ;
    RECT 120.095 0.000 120.285 90.535 ;
    RECT 120.695 0.000 120.885 90.535 ;
    RECT 121.295 0.000 121.485 90.535 ;
    RECT 121.895 0.000 122.085 90.535 ;
    RECT 122.495 0.000 122.685 90.535 ;
    RECT 123.095 0.000 123.285 90.535 ;
    RECT 123.695 0.000 123.885 90.535 ;
    RECT 124.295 0.000 124.485 90.535 ;
    RECT 124.895 0.000 125.085 90.535 ;
    RECT 125.495 0.000 125.685 90.535 ;
    RECT 126.095 0.000 126.285 90.535 ;
    RECT 126.695 0.000 126.885 90.535 ;
    RECT 127.295 0.000 127.485 90.535 ;
    RECT 127.895 0.000 128.085 90.535 ;
    RECT 128.495 0.000 128.685 90.535 ;
    RECT 129.095 0.000 129.285 90.535 ;
    RECT 129.695 0.000 129.885 90.535 ;
    RECT 130.295 0.000 130.485 90.535 ;
    RECT 130.895 0.000 131.085 90.535 ;
    RECT 131.495 0.000 131.685 90.535 ;
    RECT 132.095 0.000 132.285 90.535 ;
    RECT 132.695 0.000 132.885 90.535 ;
    RECT 133.295 0.000 133.485 90.535 ;
    RECT 133.895 0.000 134.085 90.535 ;
    RECT 134.495 0.000 134.685 90.535 ;
    RECT 135.095 0.000 135.285 90.535 ;
    RECT 135.695 0.000 135.885 90.535 ;
    RECT 136.295 0.000 136.485 90.535 ;
    RECT 136.895 0.000 137.085 90.535 ;
    RECT 137.495 0.000 137.685 90.535 ;
    RECT 138.095 0.000 138.285 90.535 ;
    RECT 138.695 0.000 138.885 90.535 ;
    RECT 139.295 0.000 139.485 90.535 ;
    RECT 139.895 0.000 140.085 90.535 ;
    RECT 140.495 0.000 140.685 90.535 ;
    RECT 141.095 0.000 141.285 90.535 ;
    RECT 141.695 0.000 141.885 90.535 ;
    RECT 142.295 0.000 142.485 90.535 ;
    RECT 142.895 0.000 143.085 90.535 ;
    RECT 143.495 0.000 143.685 90.535 ;
    RECT 144.095 0.000 144.285 90.535 ;
    RECT 144.695 0.000 144.885 90.535 ;
    RECT 145.295 0.000 145.485 90.535 ;
    RECT 145.895 0.000 146.085 90.535 ;
    RECT 146.495 0.000 146.685 90.535 ;
    RECT 147.095 0.000 147.285 90.535 ;
    RECT 147.695 0.000 147.885 90.535 ;
    RECT 148.295 0.000 148.485 90.535 ;
    RECT 148.895 0.000 149.085 90.535 ;
    RECT 149.495 0.000 149.685 90.535 ;
    RECT 150.095 0.000 150.285 90.535 ;
    RECT 150.695 0.000 150.885 90.535 ;
    RECT 151.295 0.000 151.485 90.535 ;
    RECT 151.895 0.000 152.085 90.535 ;
    RECT 152.495 0.000 152.685 90.535 ;
    RECT 153.095 0.000 153.285 90.535 ;
    RECT 153.695 0.000 153.885 90.535 ;
    RECT 154.295 0.000 154.485 90.535 ;
    RECT 154.895 0.000 155.085 90.535 ;
    RECT 155.495 0.000 155.685 90.535 ;
    RECT 156.095 0.000 156.285 90.535 ;
    RECT 156.695 0.000 156.885 90.535 ;
    RECT 157.295 0.000 157.485 90.535 ;
    RECT 157.895 0.000 158.085 90.535 ;
    RECT 158.495 0.000 158.685 90.535 ;
    RECT 159.095 0.000 159.285 90.535 ;
    RECT 159.695 0.000 159.885 90.535 ;
    RECT 160.295 0.000 160.485 90.535 ;
    RECT 160.895 0.000 161.085 90.535 ;
    RECT 161.495 0.000 161.685 90.535 ;
    RECT 162.095 0.000 162.285 90.535 ;
    RECT 162.695 0.000 162.885 90.535 ;
    RECT 163.295 0.000 163.415 90.535 ;
    RECT 163.825 0.000 163.945 90.535 ;
    RECT 164.355 0.000 164.430 90.535 ;
END
END ics55_ecos_sram_512x32_m4
END LIBRARY

